VERSION 5.8 ;
BUSBITCHARS "[]" ;
DIVIDERCHAR "/" ;
UNITS
    DATABASE MICRONS 1000 ;
END UNITS

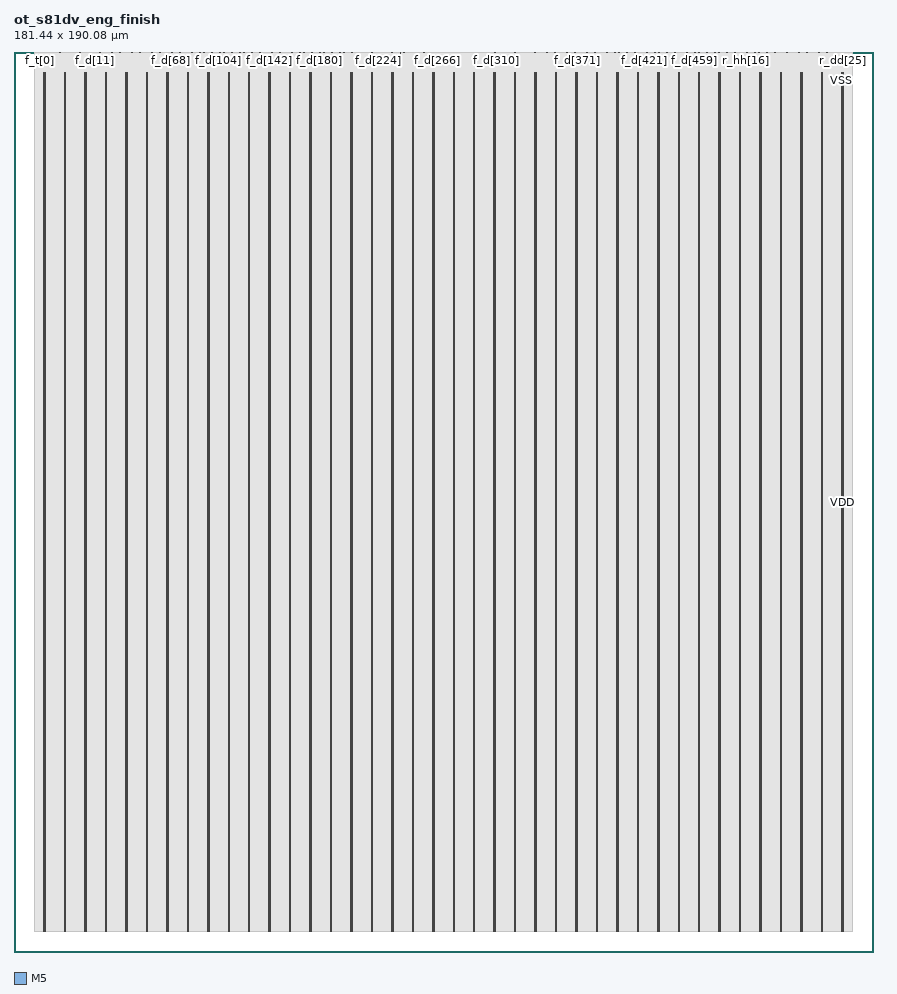
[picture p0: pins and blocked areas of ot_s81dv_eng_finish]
MACRO ot_s81dv_eng_finish
  FOREIGN ot_s81dv_eng_finish 0 0 ;
  CLASS BLOCK ;
  SIZE 181.44 BY 190.08 ;
  PIN clk
    DIRECTION INPUT ;
    USE SIGNAL ;
    PORT
      LAYER M5 ;
        RECT  81.54 189.6 81.588 190.08 ;
    END
  END clk
  PIN f_base[0]
    DIRECTION INPUT ;
    USE SIGNAL ;
    PORT
      LAYER M5 ;
        RECT  7.152 189.996 7.176 190.08 ;
    END
  END f_base[0]
  PIN f_base[10]
    DIRECTION INPUT ;
    USE SIGNAL ;
    PORT
      LAYER M5 ;
        RECT  9.936 189.996 9.96 190.08 ;
    END
  END f_base[10]
  PIN f_base[11]
    DIRECTION INPUT ;
    USE SIGNAL ;
    PORT
      LAYER M5 ;
        RECT  10.224 189.996 10.248 190.08 ;
    END
  END f_base[11]
  PIN f_base[12]
    DIRECTION INPUT ;
    USE SIGNAL ;
    PORT
      LAYER M5 ;
        RECT  10.512 189.996 10.536 190.08 ;
    END
  END f_base[12]
  PIN f_base[13]
    DIRECTION INPUT ;
    USE SIGNAL ;
    PORT
      LAYER M5 ;
        RECT  10.8 189.996 10.824 190.08 ;
    END
  END f_base[13]
  PIN f_base[14]
    DIRECTION INPUT ;
    USE SIGNAL ;
    PORT
      LAYER M5 ;
        RECT  11.088 189.996 11.112 190.08 ;
    END
  END f_base[14]
  PIN f_base[15]
    DIRECTION INPUT ;
    USE SIGNAL ;
    PORT
      LAYER M5 ;
        RECT  11.376 189.996 11.4 190.08 ;
    END
  END f_base[15]
  PIN f_base[16]
    DIRECTION INPUT ;
    USE SIGNAL ;
    PORT
      LAYER M5 ;
        RECT  11.664 189.996 11.688 190.08 ;
    END
  END f_base[16]
  PIN f_base[17]
    DIRECTION INPUT ;
    USE SIGNAL ;
    PORT
      LAYER M5 ;
        RECT  11.952 189.996 11.976 190.08 ;
    END
  END f_base[17]
  PIN f_base[18]
    DIRECTION INPUT ;
    USE SIGNAL ;
    PORT
      LAYER M5 ;
        RECT  12.192 189.996 12.216 190.08 ;
    END
  END f_base[18]
  PIN f_base[19]
    DIRECTION INPUT ;
    USE SIGNAL ;
    PORT
      LAYER M5 ;
        RECT  12.48 189.996 12.504 190.08 ;
    END
  END f_base[19]
  PIN f_base[1]
    DIRECTION INPUT ;
    USE SIGNAL ;
    PORT
      LAYER M5 ;
        RECT  7.44 189.996 7.464 190.08 ;
    END
  END f_base[1]
  PIN f_base[20]
    DIRECTION INPUT ;
    USE SIGNAL ;
    PORT
      LAYER M5 ;
        RECT  12.768 189.996 12.792 190.08 ;
    END
  END f_base[20]
  PIN f_base[21]
    DIRECTION INPUT ;
    USE SIGNAL ;
    PORT
      LAYER M5 ;
        RECT  13.056 189.996 13.08 190.08 ;
    END
  END f_base[21]
  PIN f_base[22]
    DIRECTION INPUT ;
    USE SIGNAL ;
    PORT
      LAYER M5 ;
        RECT  13.344 189.996 13.368 190.08 ;
    END
  END f_base[22]
  PIN f_base[23]
    DIRECTION INPUT ;
    USE SIGNAL ;
    PORT
      LAYER M5 ;
        RECT  13.632 189.996 13.656 190.08 ;
    END
  END f_base[23]
  PIN f_base[2]
    DIRECTION INPUT ;
    USE SIGNAL ;
    PORT
      LAYER M5 ;
        RECT  7.68 189.996 7.704 190.08 ;
    END
  END f_base[2]
  PIN f_base[3]
    DIRECTION INPUT ;
    USE SIGNAL ;
    PORT
      LAYER M5 ;
        RECT  7.968 189.996 7.992 190.08 ;
    END
  END f_base[3]
  PIN f_base[4]
    DIRECTION INPUT ;
    USE SIGNAL ;
    PORT
      LAYER M5 ;
        RECT  8.256 189.996 8.28 190.08 ;
    END
  END f_base[4]
  PIN f_base[5]
    DIRECTION INPUT ;
    USE SIGNAL ;
    PORT
      LAYER M5 ;
        RECT  8.544 189.996 8.568 190.08 ;
    END
  END f_base[5]
  PIN f_base[6]
    DIRECTION INPUT ;
    USE SIGNAL ;
    PORT
      LAYER M5 ;
        RECT  8.832 189.996 8.856 190.08 ;
    END
  END f_base[6]
  PIN f_base[7]
    DIRECTION INPUT ;
    USE SIGNAL ;
    PORT
      LAYER M5 ;
        RECT  9.12 189.996 9.144 190.08 ;
    END
  END f_base[7]
  PIN f_base[8]
    DIRECTION INPUT ;
    USE SIGNAL ;
    PORT
      LAYER M5 ;
        RECT  9.408 189.996 9.432 190.08 ;
    END
  END f_base[8]
  PIN f_base[9]
    DIRECTION INPUT ;
    USE SIGNAL ;
    PORT
      LAYER M5 ;
        RECT  9.696 189.996 9.72 190.08 ;
    END
  END f_base[9]
  PIN f_d[0]
    DIRECTION INPUT ;
    USE SIGNAL ;
    PORT
      LAYER M5 ;
        RECT  13.92 189.996 13.944 190.08 ;
    END
  END f_d[0]
  PIN f_d[100]
    DIRECTION INPUT ;
    USE SIGNAL ;
    PORT
      LAYER M5 ;
        RECT  42.096 189.996 42.12 190.08 ;
    END
  END f_d[100]
  PIN f_d[101]
    DIRECTION INPUT ;
    USE SIGNAL ;
    PORT
      LAYER M5 ;
        RECT  42.384 189.996 42.408 190.08 ;
    END
  END f_d[101]
  PIN f_d[102]
    DIRECTION INPUT ;
    USE SIGNAL ;
    PORT
      LAYER M5 ;
        RECT  42.624 189.996 42.648 190.08 ;
    END
  END f_d[102]
  PIN f_d[103]
    DIRECTION INPUT ;
    USE SIGNAL ;
    PORT
      LAYER M5 ;
        RECT  42.912 189.996 42.936 190.08 ;
    END
  END f_d[103]
  PIN f_d[104]
    DIRECTION INPUT ;
    USE SIGNAL ;
    PORT
      LAYER M5 ;
        RECT  43.2 189.996 43.224 190.08 ;
    END
  END f_d[104]
  PIN f_d[105]
    DIRECTION INPUT ;
    USE SIGNAL ;
    PORT
      LAYER M5 ;
        RECT  43.488 189.996 43.512 190.08 ;
    END
  END f_d[105]
  PIN f_d[106]
    DIRECTION INPUT ;
    USE SIGNAL ;
    PORT
      LAYER M5 ;
        RECT  43.776 189.996 43.8 190.08 ;
    END
  END f_d[106]
  PIN f_d[107]
    DIRECTION INPUT ;
    USE SIGNAL ;
    PORT
      LAYER M5 ;
        RECT  44.064 189.996 44.088 190.08 ;
    END
  END f_d[107]
  PIN f_d[108]
    DIRECTION INPUT ;
    USE SIGNAL ;
    PORT
      LAYER M5 ;
        RECT  44.352 189.996 44.376 190.08 ;
    END
  END f_d[108]
  PIN f_d[109]
    DIRECTION INPUT ;
    USE SIGNAL ;
    PORT
      LAYER M5 ;
        RECT  44.64 189.996 44.664 190.08 ;
    END
  END f_d[109]
  PIN f_d[10]
    DIRECTION INPUT ;
    USE SIGNAL ;
    PORT
      LAYER M5 ;
        RECT  16.704 189.996 16.728 190.08 ;
    END
  END f_d[10]
  PIN f_d[110]
    DIRECTION INPUT ;
    USE SIGNAL ;
    PORT
      LAYER M5 ;
        RECT  44.88 189.996 44.904 190.08 ;
    END
  END f_d[110]
  PIN f_d[111]
    DIRECTION INPUT ;
    USE SIGNAL ;
    PORT
      LAYER M5 ;
        RECT  45.168 189.996 45.192 190.08 ;
    END
  END f_d[111]
  PIN f_d[112]
    DIRECTION INPUT ;
    USE SIGNAL ;
    PORT
      LAYER M5 ;
        RECT  45.456 189.996 45.48 190.08 ;
    END
  END f_d[112]
  PIN f_d[113]
    DIRECTION INPUT ;
    USE SIGNAL ;
    PORT
      LAYER M5 ;
        RECT  45.744 189.996 45.768 190.08 ;
    END
  END f_d[113]
  PIN f_d[114]
    DIRECTION INPUT ;
    USE SIGNAL ;
    PORT
      LAYER M5 ;
        RECT  46.032 189.996 46.056 190.08 ;
    END
  END f_d[114]
  PIN f_d[115]
    DIRECTION INPUT ;
    USE SIGNAL ;
    PORT
      LAYER M5 ;
        RECT  46.32 189.996 46.344 190.08 ;
    END
  END f_d[115]
  PIN f_d[116]
    DIRECTION INPUT ;
    USE SIGNAL ;
    PORT
      LAYER M5 ;
        RECT  46.608 189.996 46.632 190.08 ;
    END
  END f_d[116]
  PIN f_d[117]
    DIRECTION INPUT ;
    USE SIGNAL ;
    PORT
      LAYER M5 ;
        RECT  46.896 189.996 46.92 190.08 ;
    END
  END f_d[117]
  PIN f_d[118]
    DIRECTION INPUT ;
    USE SIGNAL ;
    PORT
      LAYER M5 ;
        RECT  47.136 189.996 47.16 190.08 ;
    END
  END f_d[118]
  PIN f_d[119]
    DIRECTION INPUT ;
    USE SIGNAL ;
    PORT
      LAYER M5 ;
        RECT  47.424 189.996 47.448 190.08 ;
    END
  END f_d[119]
  PIN f_d[11]
    DIRECTION INPUT ;
    USE SIGNAL ;
    PORT
      LAYER M5 ;
        RECT  16.992 189.996 17.016 190.08 ;
    END
  END f_d[11]
  PIN f_d[120]
    DIRECTION INPUT ;
    USE SIGNAL ;
    PORT
      LAYER M5 ;
        RECT  47.712 189.996 47.736 190.08 ;
    END
  END f_d[120]
  PIN f_d[121]
    DIRECTION INPUT ;
    USE SIGNAL ;
    PORT
      LAYER M5 ;
        RECT  48 189.996 48.024 190.08 ;
    END
  END f_d[121]
  PIN f_d[122]
    DIRECTION INPUT ;
    USE SIGNAL ;
    PORT
      LAYER M5 ;
        RECT  48.288 189.996 48.312 190.08 ;
    END
  END f_d[122]
  PIN f_d[123]
    DIRECTION INPUT ;
    USE SIGNAL ;
    PORT
      LAYER M5 ;
        RECT  48.576 189.996 48.6 190.08 ;
    END
  END f_d[123]
  PIN f_d[124]
    DIRECTION INPUT ;
    USE SIGNAL ;
    PORT
      LAYER M5 ;
        RECT  48.864 189.996 48.888 190.08 ;
    END
  END f_d[124]
  PIN f_d[125]
    DIRECTION INPUT ;
    USE SIGNAL ;
    PORT
      LAYER M5 ;
        RECT  49.152 189.996 49.176 190.08 ;
    END
  END f_d[125]
  PIN f_d[126]
    DIRECTION INPUT ;
    USE SIGNAL ;
    PORT
      LAYER M5 ;
        RECT  49.392 189.996 49.416 190.08 ;
    END
  END f_d[126]
  PIN f_d[127]
    DIRECTION INPUT ;
    USE SIGNAL ;
    PORT
      LAYER M5 ;
        RECT  49.68 189.996 49.704 190.08 ;
    END
  END f_d[127]
  PIN f_d[128]
    DIRECTION INPUT ;
    USE SIGNAL ;
    PORT
      LAYER M5 ;
        RECT  49.968 189.996 49.992 190.08 ;
    END
  END f_d[128]
  PIN f_d[129]
    DIRECTION INPUT ;
    USE SIGNAL ;
    PORT
      LAYER M5 ;
        RECT  50.256 189.996 50.28 190.08 ;
    END
  END f_d[129]
  PIN f_d[12]
    DIRECTION INPUT ;
    USE SIGNAL ;
    PORT
      LAYER M5 ;
        RECT  17.28 189.996 17.304 190.08 ;
    END
  END f_d[12]
  PIN f_d[130]
    DIRECTION INPUT ;
    USE SIGNAL ;
    PORT
      LAYER M5 ;
        RECT  50.544 189.996 50.568 190.08 ;
    END
  END f_d[130]
  PIN f_d[131]
    DIRECTION INPUT ;
    USE SIGNAL ;
    PORT
      LAYER M5 ;
        RECT  50.832 189.996 50.856 190.08 ;
    END
  END f_d[131]
  PIN f_d[132]
    DIRECTION INPUT ;
    USE SIGNAL ;
    PORT
      LAYER M5 ;
        RECT  51.12 189.996 51.144 190.08 ;
    END
  END f_d[132]
  PIN f_d[133]
    DIRECTION INPUT ;
    USE SIGNAL ;
    PORT
      LAYER M5 ;
        RECT  51.36 189.996 51.384 190.08 ;
    END
  END f_d[133]
  PIN f_d[134]
    DIRECTION INPUT ;
    USE SIGNAL ;
    PORT
      LAYER M5 ;
        RECT  51.648 189.996 51.672 190.08 ;
    END
  END f_d[134]
  PIN f_d[135]
    DIRECTION INPUT ;
    USE SIGNAL ;
    PORT
      LAYER M5 ;
        RECT  51.936 189.996 51.96 190.08 ;
    END
  END f_d[135]
  PIN f_d[136]
    DIRECTION INPUT ;
    USE SIGNAL ;
    PORT
      LAYER M5 ;
        RECT  52.224 189.996 52.248 190.08 ;
    END
  END f_d[136]
  PIN f_d[137]
    DIRECTION INPUT ;
    USE SIGNAL ;
    PORT
      LAYER M5 ;
        RECT  52.512 189.996 52.536 190.08 ;
    END
  END f_d[137]
  PIN f_d[138]
    DIRECTION INPUT ;
    USE SIGNAL ;
    PORT
      LAYER M5 ;
        RECT  52.8 189.996 52.824 190.08 ;
    END
  END f_d[138]
  PIN f_d[139]
    DIRECTION INPUT ;
    USE SIGNAL ;
    PORT
      LAYER M5 ;
        RECT  53.088 189.996 53.112 190.08 ;
    END
  END f_d[139]
  PIN f_d[13]
    DIRECTION INPUT ;
    USE SIGNAL ;
    PORT
      LAYER M5 ;
        RECT  17.568 189.996 17.592 190.08 ;
    END
  END f_d[13]
  PIN f_d[140]
    DIRECTION INPUT ;
    USE SIGNAL ;
    PORT
      LAYER M5 ;
        RECT  53.376 189.996 53.4 190.08 ;
    END
  END f_d[140]
  PIN f_d[141]
    DIRECTION INPUT ;
    USE SIGNAL ;
    PORT
      LAYER M5 ;
        RECT  53.616 189.996 53.64 190.08 ;
    END
  END f_d[141]
  PIN f_d[142]
    DIRECTION INPUT ;
    USE SIGNAL ;
    PORT
      LAYER M5 ;
        RECT  53.904 189.996 53.928 190.08 ;
    END
  END f_d[142]
  PIN f_d[143]
    DIRECTION INPUT ;
    USE SIGNAL ;
    PORT
      LAYER M5 ;
        RECT  54.192 189.996 54.216 190.08 ;
    END
  END f_d[143]
  PIN f_d[144]
    DIRECTION INPUT ;
    USE SIGNAL ;
    PORT
      LAYER M5 ;
        RECT  54.48 189.996 54.504 190.08 ;
    END
  END f_d[144]
  PIN f_d[145]
    DIRECTION INPUT ;
    USE SIGNAL ;
    PORT
      LAYER M5 ;
        RECT  54.768 189.996 54.792 190.08 ;
    END
  END f_d[145]
  PIN f_d[146]
    DIRECTION INPUT ;
    USE SIGNAL ;
    PORT
      LAYER M5 ;
        RECT  55.056 189.996 55.08 190.08 ;
    END
  END f_d[146]
  PIN f_d[147]
    DIRECTION INPUT ;
    USE SIGNAL ;
    PORT
      LAYER M5 ;
        RECT  55.344 189.996 55.368 190.08 ;
    END
  END f_d[147]
  PIN f_d[148]
    DIRECTION INPUT ;
    USE SIGNAL ;
    PORT
      LAYER M5 ;
        RECT  55.632 189.996 55.656 190.08 ;
    END
  END f_d[148]
  PIN f_d[149]
    DIRECTION INPUT ;
    USE SIGNAL ;
    PORT
      LAYER M5 ;
        RECT  55.872 189.996 55.896 190.08 ;
    END
  END f_d[149]
  PIN f_d[14]
    DIRECTION INPUT ;
    USE SIGNAL ;
    PORT
      LAYER M5 ;
        RECT  17.856 189.996 17.88 190.08 ;
    END
  END f_d[14]
  PIN f_d[150]
    DIRECTION INPUT ;
    USE SIGNAL ;
    PORT
      LAYER M5 ;
        RECT  56.16 189.996 56.184 190.08 ;
    END
  END f_d[150]
  PIN f_d[151]
    DIRECTION INPUT ;
    USE SIGNAL ;
    PORT
      LAYER M5 ;
        RECT  56.448 189.996 56.472 190.08 ;
    END
  END f_d[151]
  PIN f_d[152]
    DIRECTION INPUT ;
    USE SIGNAL ;
    PORT
      LAYER M5 ;
        RECT  56.736 189.996 56.76 190.08 ;
    END
  END f_d[152]
  PIN f_d[153]
    DIRECTION INPUT ;
    USE SIGNAL ;
    PORT
      LAYER M5 ;
        RECT  57.024 189.996 57.048 190.08 ;
    END
  END f_d[153]
  PIN f_d[154]
    DIRECTION INPUT ;
    USE SIGNAL ;
    PORT
      LAYER M5 ;
        RECT  57.312 189.996 57.336 190.08 ;
    END
  END f_d[154]
  PIN f_d[155]
    DIRECTION INPUT ;
    USE SIGNAL ;
    PORT
      LAYER M5 ;
        RECT  57.6 189.996 57.624 190.08 ;
    END
  END f_d[155]
  PIN f_d[156]
    DIRECTION INPUT ;
    USE SIGNAL ;
    PORT
      LAYER M5 ;
        RECT  57.888 189.996 57.912 190.08 ;
    END
  END f_d[156]
  PIN f_d[157]
    DIRECTION INPUT ;
    USE SIGNAL ;
    PORT
      LAYER M5 ;
        RECT  58.128 189.996 58.152 190.08 ;
    END
  END f_d[157]
  PIN f_d[158]
    DIRECTION INPUT ;
    USE SIGNAL ;
    PORT
      LAYER M5 ;
        RECT  58.416 189.996 58.44 190.08 ;
    END
  END f_d[158]
  PIN f_d[159]
    DIRECTION INPUT ;
    USE SIGNAL ;
    PORT
      LAYER M5 ;
        RECT  58.704 189.996 58.728 190.08 ;
    END
  END f_d[159]
  PIN f_d[15]
    DIRECTION INPUT ;
    USE SIGNAL ;
    PORT
      LAYER M5 ;
        RECT  18.144 189.996 18.168 190.08 ;
    END
  END f_d[15]
  PIN f_d[160]
    DIRECTION INPUT ;
    USE SIGNAL ;
    PORT
      LAYER M5 ;
        RECT  58.992 189.996 59.016 190.08 ;
    END
  END f_d[160]
  PIN f_d[161]
    DIRECTION INPUT ;
    USE SIGNAL ;
    PORT
      LAYER M5 ;
        RECT  59.28 189.996 59.304 190.08 ;
    END
  END f_d[161]
  PIN f_d[162]
    DIRECTION INPUT ;
    USE SIGNAL ;
    PORT
      LAYER M5 ;
        RECT  59.568 189.996 59.592 190.08 ;
    END
  END f_d[162]
  PIN f_d[163]
    DIRECTION INPUT ;
    USE SIGNAL ;
    PORT
      LAYER M5 ;
        RECT  59.856 189.996 59.88 190.08 ;
    END
  END f_d[163]
  PIN f_d[164]
    DIRECTION INPUT ;
    USE SIGNAL ;
    PORT
      LAYER M5 ;
        RECT  60.096 189.996 60.12 190.08 ;
    END
  END f_d[164]
  PIN f_d[165]
    DIRECTION INPUT ;
    USE SIGNAL ;
    PORT
      LAYER M5 ;
        RECT  60.384 189.996 60.408 190.08 ;
    END
  END f_d[165]
  PIN f_d[166]
    DIRECTION INPUT ;
    USE SIGNAL ;
    PORT
      LAYER M5 ;
        RECT  60.672 189.996 60.696 190.08 ;
    END
  END f_d[166]
  PIN f_d[167]
    DIRECTION INPUT ;
    USE SIGNAL ;
    PORT
      LAYER M5 ;
        RECT  60.96 189.996 60.984 190.08 ;
    END
  END f_d[167]
  PIN f_d[168]
    DIRECTION INPUT ;
    USE SIGNAL ;
    PORT
      LAYER M5 ;
        RECT  61.248 189.996 61.272 190.08 ;
    END
  END f_d[168]
  PIN f_d[169]
    DIRECTION INPUT ;
    USE SIGNAL ;
    PORT
      LAYER M5 ;
        RECT  61.536 189.996 61.56 190.08 ;
    END
  END f_d[169]
  PIN f_d[16]
    DIRECTION INPUT ;
    USE SIGNAL ;
    PORT
      LAYER M5 ;
        RECT  18.432 189.996 18.456 190.08 ;
    END
  END f_d[16]
  PIN f_d[170]
    DIRECTION INPUT ;
    USE SIGNAL ;
    PORT
      LAYER M5 ;
        RECT  61.824 189.996 61.848 190.08 ;
    END
  END f_d[170]
  PIN f_d[171]
    DIRECTION INPUT ;
    USE SIGNAL ;
    PORT
      LAYER M5 ;
        RECT  62.112 189.996 62.136 190.08 ;
    END
  END f_d[171]
  PIN f_d[172]
    DIRECTION INPUT ;
    USE SIGNAL ;
    PORT
      LAYER M5 ;
        RECT  62.352 189.996 62.376 190.08 ;
    END
  END f_d[172]
  PIN f_d[173]
    DIRECTION INPUT ;
    USE SIGNAL ;
    PORT
      LAYER M5 ;
        RECT  62.64 189.996 62.664 190.08 ;
    END
  END f_d[173]
  PIN f_d[174]
    DIRECTION INPUT ;
    USE SIGNAL ;
    PORT
      LAYER M5 ;
        RECT  62.928 189.996 62.952 190.08 ;
    END
  END f_d[174]
  PIN f_d[175]
    DIRECTION INPUT ;
    USE SIGNAL ;
    PORT
      LAYER M5 ;
        RECT  63.216 189.996 63.24 190.08 ;
    END
  END f_d[175]
  PIN f_d[176]
    DIRECTION INPUT ;
    USE SIGNAL ;
    PORT
      LAYER M5 ;
        RECT  63.504 189.996 63.528 190.08 ;
    END
  END f_d[176]
  PIN f_d[177]
    DIRECTION INPUT ;
    USE SIGNAL ;
    PORT
      LAYER M5 ;
        RECT  63.792 189.996 63.816 190.08 ;
    END
  END f_d[177]
  PIN f_d[178]
    DIRECTION INPUT ;
    USE SIGNAL ;
    PORT
      LAYER M5 ;
        RECT  64.08 189.996 64.104 190.08 ;
    END
  END f_d[178]
  PIN f_d[179]
    DIRECTION INPUT ;
    USE SIGNAL ;
    PORT
      LAYER M5 ;
        RECT  64.368 189.996 64.392 190.08 ;
    END
  END f_d[179]
  PIN f_d[17]
    DIRECTION INPUT ;
    USE SIGNAL ;
    PORT
      LAYER M5 ;
        RECT  18.672 189.996 18.696 190.08 ;
    END
  END f_d[17]
  PIN f_d[180]
    DIRECTION INPUT ;
    USE SIGNAL ;
    PORT
      LAYER M5 ;
        RECT  64.608 189.996 64.632 190.08 ;
    END
  END f_d[180]
  PIN f_d[181]
    DIRECTION INPUT ;
    USE SIGNAL ;
    PORT
      LAYER M5 ;
        RECT  64.896 189.996 64.92 190.08 ;
    END
  END f_d[181]
  PIN f_d[182]
    DIRECTION INPUT ;
    USE SIGNAL ;
    PORT
      LAYER M5 ;
        RECT  65.184 189.996 65.208 190.08 ;
    END
  END f_d[182]
  PIN f_d[183]
    DIRECTION INPUT ;
    USE SIGNAL ;
    PORT
      LAYER M5 ;
        RECT  65.472 189.996 65.496 190.08 ;
    END
  END f_d[183]
  PIN f_d[184]
    DIRECTION INPUT ;
    USE SIGNAL ;
    PORT
      LAYER M5 ;
        RECT  65.76 189.996 65.784 190.08 ;
    END
  END f_d[184]
  PIN f_d[185]
    DIRECTION INPUT ;
    USE SIGNAL ;
    PORT
      LAYER M5 ;
        RECT  66.048 189.996 66.072 190.08 ;
    END
  END f_d[185]
  PIN f_d[186]
    DIRECTION INPUT ;
    USE SIGNAL ;
    PORT
      LAYER M5 ;
        RECT  66.336 189.996 66.36 190.08 ;
    END
  END f_d[186]
  PIN f_d[187]
    DIRECTION INPUT ;
    USE SIGNAL ;
    PORT
      LAYER M5 ;
        RECT  66.624 189.996 66.648 190.08 ;
    END
  END f_d[187]
  PIN f_d[188]
    DIRECTION INPUT ;
    USE SIGNAL ;
    PORT
      LAYER M5 ;
        RECT  66.864 189.996 66.888 190.08 ;
    END
  END f_d[188]
  PIN f_d[189]
    DIRECTION INPUT ;
    USE SIGNAL ;
    PORT
      LAYER M5 ;
        RECT  67.152 189.996 67.176 190.08 ;
    END
  END f_d[189]
  PIN f_d[18]
    DIRECTION INPUT ;
    USE SIGNAL ;
    PORT
      LAYER M5 ;
        RECT  18.96 189.996 18.984 190.08 ;
    END
  END f_d[18]
  PIN f_d[190]
    DIRECTION INPUT ;
    USE SIGNAL ;
    PORT
      LAYER M5 ;
        RECT  67.44 189.996 67.464 190.08 ;
    END
  END f_d[190]
  PIN f_d[191]
    DIRECTION INPUT ;
    USE SIGNAL ;
    PORT
      LAYER M5 ;
        RECT  67.728 189.996 67.752 190.08 ;
    END
  END f_d[191]
  PIN f_d[192]
    DIRECTION INPUT ;
    USE SIGNAL ;
    PORT
      LAYER M5 ;
        RECT  68.016 189.996 68.04 190.08 ;
    END
  END f_d[192]
  PIN f_d[193]
    DIRECTION INPUT ;
    USE SIGNAL ;
    PORT
      LAYER M5 ;
        RECT  68.304 189.996 68.328 190.08 ;
    END
  END f_d[193]
  PIN f_d[194]
    DIRECTION INPUT ;
    USE SIGNAL ;
    PORT
      LAYER M5 ;
        RECT  68.592 189.996 68.616 190.08 ;
    END
  END f_d[194]
  PIN f_d[195]
    DIRECTION INPUT ;
    USE SIGNAL ;
    PORT
      LAYER M5 ;
        RECT  68.832 189.996 68.856 190.08 ;
    END
  END f_d[195]
  PIN f_d[196]
    DIRECTION INPUT ;
    USE SIGNAL ;
    PORT
      LAYER M5 ;
        RECT  69.12 189.996 69.144 190.08 ;
    END
  END f_d[196]
  PIN f_d[197]
    DIRECTION INPUT ;
    USE SIGNAL ;
    PORT
      LAYER M5 ;
        RECT  69.408 189.996 69.432 190.08 ;
    END
  END f_d[197]
  PIN f_d[198]
    DIRECTION INPUT ;
    USE SIGNAL ;
    PORT
      LAYER M5 ;
        RECT  69.696 189.996 69.72 190.08 ;
    END
  END f_d[198]
  PIN f_d[199]
    DIRECTION INPUT ;
    USE SIGNAL ;
    PORT
      LAYER M5 ;
        RECT  69.984 189.996 70.008 190.08 ;
    END
  END f_d[199]
  PIN f_d[19]
    DIRECTION INPUT ;
    USE SIGNAL ;
    PORT
      LAYER M5 ;
        RECT  19.248 189.996 19.272 190.08 ;
    END
  END f_d[19]
  PIN f_d[1]
    DIRECTION INPUT ;
    USE SIGNAL ;
    PORT
      LAYER M5 ;
        RECT  14.16 189.996 14.184 190.08 ;
    END
  END f_d[1]
  PIN f_d[200]
    DIRECTION INPUT ;
    USE SIGNAL ;
    PORT
      LAYER M5 ;
        RECT  70.272 189.996 70.296 190.08 ;
    END
  END f_d[200]
  PIN f_d[201]
    DIRECTION INPUT ;
    USE SIGNAL ;
    PORT
      LAYER M5 ;
        RECT  70.56 189.996 70.584 190.08 ;
    END
  END f_d[201]
  PIN f_d[202]
    DIRECTION INPUT ;
    USE SIGNAL ;
    PORT
      LAYER M5 ;
        RECT  70.848 189.996 70.872 190.08 ;
    END
  END f_d[202]
  PIN f_d[203]
    DIRECTION INPUT ;
    USE SIGNAL ;
    PORT
      LAYER M5 ;
        RECT  71.088 189.996 71.112 190.08 ;
    END
  END f_d[203]
  PIN f_d[204]
    DIRECTION INPUT ;
    USE SIGNAL ;
    PORT
      LAYER M5 ;
        RECT  71.376 189.996 71.4 190.08 ;
    END
  END f_d[204]
  PIN f_d[205]
    DIRECTION INPUT ;
    USE SIGNAL ;
    PORT
      LAYER M5 ;
        RECT  71.664 189.996 71.688 190.08 ;
    END
  END f_d[205]
  PIN f_d[206]
    DIRECTION INPUT ;
    USE SIGNAL ;
    PORT
      LAYER M5 ;
        RECT  71.952 189.996 71.976 190.08 ;
    END
  END f_d[206]
  PIN f_d[207]
    DIRECTION INPUT ;
    USE SIGNAL ;
    PORT
      LAYER M5 ;
        RECT  72.24 189.996 72.264 190.08 ;
    END
  END f_d[207]
  PIN f_d[208]
    DIRECTION INPUT ;
    USE SIGNAL ;
    PORT
      LAYER M5 ;
        RECT  72.528 189.996 72.552 190.08 ;
    END
  END f_d[208]
  PIN f_d[209]
    DIRECTION INPUT ;
    USE SIGNAL ;
    PORT
      LAYER M5 ;
        RECT  72.816 189.996 72.84 190.08 ;
    END
  END f_d[209]
  PIN f_d[20]
    DIRECTION INPUT ;
    USE SIGNAL ;
    PORT
      LAYER M5 ;
        RECT  19.536 189.996 19.56 190.08 ;
    END
  END f_d[20]
  PIN f_d[210]
    DIRECTION INPUT ;
    USE SIGNAL ;
    PORT
      LAYER M5 ;
        RECT  73.104 189.996 73.128 190.08 ;
    END
  END f_d[210]
  PIN f_d[211]
    DIRECTION INPUT ;
    USE SIGNAL ;
    PORT
      LAYER M5 ;
        RECT  73.344 189.996 73.368 190.08 ;
    END
  END f_d[211]
  PIN f_d[212]
    DIRECTION INPUT ;
    USE SIGNAL ;
    PORT
      LAYER M5 ;
        RECT  73.632 189.996 73.656 190.08 ;
    END
  END f_d[212]
  PIN f_d[213]
    DIRECTION INPUT ;
    USE SIGNAL ;
    PORT
      LAYER M5 ;
        RECT  73.92 189.996 73.944 190.08 ;
    END
  END f_d[213]
  PIN f_d[214]
    DIRECTION INPUT ;
    USE SIGNAL ;
    PORT
      LAYER M5 ;
        RECT  74.208 189.996 74.232 190.08 ;
    END
  END f_d[214]
  PIN f_d[215]
    DIRECTION INPUT ;
    USE SIGNAL ;
    PORT
      LAYER M5 ;
        RECT  74.496 189.996 74.52 190.08 ;
    END
  END f_d[215]
  PIN f_d[216]
    DIRECTION INPUT ;
    USE SIGNAL ;
    PORT
      LAYER M5 ;
        RECT  74.784 189.996 74.808 190.08 ;
    END
  END f_d[216]
  PIN f_d[217]
    DIRECTION INPUT ;
    USE SIGNAL ;
    PORT
      LAYER M5 ;
        RECT  75.072 189.996 75.096 190.08 ;
    END
  END f_d[217]
  PIN f_d[218]
    DIRECTION INPUT ;
    USE SIGNAL ;
    PORT
      LAYER M5 ;
        RECT  75.36 189.996 75.384 190.08 ;
    END
  END f_d[218]
  PIN f_d[219]
    DIRECTION INPUT ;
    USE SIGNAL ;
    PORT
      LAYER M5 ;
        RECT  75.6 189.996 75.624 190.08 ;
    END
  END f_d[219]
  PIN f_d[21]
    DIRECTION INPUT ;
    USE SIGNAL ;
    PORT
      LAYER M5 ;
        RECT  19.824 189.996 19.848 190.08 ;
    END
  END f_d[21]
  PIN f_d[220]
    DIRECTION INPUT ;
    USE SIGNAL ;
    PORT
      LAYER M5 ;
        RECT  75.888 189.996 75.912 190.08 ;
    END
  END f_d[220]
  PIN f_d[221]
    DIRECTION INPUT ;
    USE SIGNAL ;
    PORT
      LAYER M5 ;
        RECT  76.176 189.996 76.2 190.08 ;
    END
  END f_d[221]
  PIN f_d[222]
    DIRECTION INPUT ;
    USE SIGNAL ;
    PORT
      LAYER M5 ;
        RECT  76.464 189.996 76.488 190.08 ;
    END
  END f_d[222]
  PIN f_d[223]
    DIRECTION INPUT ;
    USE SIGNAL ;
    PORT
      LAYER M5 ;
        RECT  76.752 189.996 76.776 190.08 ;
    END
  END f_d[223]
  PIN f_d[224]
    DIRECTION INPUT ;
    USE SIGNAL ;
    PORT
      LAYER M5 ;
        RECT  77.04 189.996 77.064 190.08 ;
    END
  END f_d[224]
  PIN f_d[225]
    DIRECTION INPUT ;
    USE SIGNAL ;
    PORT
      LAYER M5 ;
        RECT  77.328 189.996 77.352 190.08 ;
    END
  END f_d[225]
  PIN f_d[226]
    DIRECTION INPUT ;
    USE SIGNAL ;
    PORT
      LAYER M5 ;
        RECT  77.568 189.996 77.592 190.08 ;
    END
  END f_d[226]
  PIN f_d[227]
    DIRECTION INPUT ;
    USE SIGNAL ;
    PORT
      LAYER M5 ;
        RECT  77.856 189.996 77.88 190.08 ;
    END
  END f_d[227]
  PIN f_d[228]
    DIRECTION INPUT ;
    USE SIGNAL ;
    PORT
      LAYER M5 ;
        RECT  78.144 189.996 78.168 190.08 ;
    END
  END f_d[228]
  PIN f_d[229]
    DIRECTION INPUT ;
    USE SIGNAL ;
    PORT
      LAYER M5 ;
        RECT  78.432 189.996 78.456 190.08 ;
    END
  END f_d[229]
  PIN f_d[22]
    DIRECTION INPUT ;
    USE SIGNAL ;
    PORT
      LAYER M5 ;
        RECT  20.112 189.996 20.136 190.08 ;
    END
  END f_d[22]
  PIN f_d[230]
    DIRECTION INPUT ;
    USE SIGNAL ;
    PORT
      LAYER M5 ;
        RECT  78.72 189.996 78.744 190.08 ;
    END
  END f_d[230]
  PIN f_d[231]
    DIRECTION INPUT ;
    USE SIGNAL ;
    PORT
      LAYER M5 ;
        RECT  79.008 189.996 79.032 190.08 ;
    END
  END f_d[231]
  PIN f_d[232]
    DIRECTION INPUT ;
    USE SIGNAL ;
    PORT
      LAYER M5 ;
        RECT  79.296 189.996 79.32 190.08 ;
    END
  END f_d[232]
  PIN f_d[233]
    DIRECTION INPUT ;
    USE SIGNAL ;
    PORT
      LAYER M5 ;
        RECT  79.584 189.996 79.608 190.08 ;
    END
  END f_d[233]
  PIN f_d[234]
    DIRECTION INPUT ;
    USE SIGNAL ;
    PORT
      LAYER M5 ;
        RECT  79.824 189.996 79.848 190.08 ;
    END
  END f_d[234]
  PIN f_d[235]
    DIRECTION INPUT ;
    USE SIGNAL ;
    PORT
      LAYER M5 ;
        RECT  80.112 189.996 80.136 190.08 ;
    END
  END f_d[235]
  PIN f_d[236]
    DIRECTION INPUT ;
    USE SIGNAL ;
    PORT
      LAYER M5 ;
        RECT  80.4 189.996 80.424 190.08 ;
    END
  END f_d[236]
  PIN f_d[237]
    DIRECTION INPUT ;
    USE SIGNAL ;
    PORT
      LAYER M5 ;
        RECT  80.688 189.996 80.712 190.08 ;
    END
  END f_d[237]
  PIN f_d[238]
    DIRECTION INPUT ;
    USE SIGNAL ;
    PORT
      LAYER M5 ;
        RECT  80.976 189.996 81 190.08 ;
    END
  END f_d[238]
  PIN f_d[239]
    DIRECTION INPUT ;
    USE SIGNAL ;
    PORT
      LAYER M5 ;
        RECT  81.264 189.996 81.288 190.08 ;
    END
  END f_d[239]
  PIN f_d[23]
    DIRECTION INPUT ;
    USE SIGNAL ;
    PORT
      LAYER M5 ;
        RECT  20.4 189.996 20.424 190.08 ;
    END
  END f_d[23]
  PIN f_d[240]
    DIRECTION INPUT ;
    USE SIGNAL ;
    PORT
      LAYER M5 ;
        RECT  82.08 189.996 82.104 190.08 ;
    END
  END f_d[240]
  PIN f_d[241]
    DIRECTION INPUT ;
    USE SIGNAL ;
    PORT
      LAYER M5 ;
        RECT  82.368 189.996 82.392 190.08 ;
    END
  END f_d[241]
  PIN f_d[242]
    DIRECTION INPUT ;
    USE SIGNAL ;
    PORT
      LAYER M5 ;
        RECT  82.656 189.996 82.68 190.08 ;
    END
  END f_d[242]
  PIN f_d[243]
    DIRECTION INPUT ;
    USE SIGNAL ;
    PORT
      LAYER M5 ;
        RECT  82.944 189.996 82.968 190.08 ;
    END
  END f_d[243]
  PIN f_d[244]
    DIRECTION INPUT ;
    USE SIGNAL ;
    PORT
      LAYER M5 ;
        RECT  83.232 189.996 83.256 190.08 ;
    END
  END f_d[244]
  PIN f_d[245]
    DIRECTION INPUT ;
    USE SIGNAL ;
    PORT
      LAYER M5 ;
        RECT  83.52 189.996 83.544 190.08 ;
    END
  END f_d[245]
  PIN f_d[246]
    DIRECTION INPUT ;
    USE SIGNAL ;
    PORT
      LAYER M5 ;
        RECT  83.808 189.996 83.832 190.08 ;
    END
  END f_d[246]
  PIN f_d[247]
    DIRECTION INPUT ;
    USE SIGNAL ;
    PORT
      LAYER M5 ;
        RECT  84.096 189.996 84.12 190.08 ;
    END
  END f_d[247]
  PIN f_d[248]
    DIRECTION INPUT ;
    USE SIGNAL ;
    PORT
      LAYER M5 ;
        RECT  84.336 189.996 84.36 190.08 ;
    END
  END f_d[248]
  PIN f_d[249]
    DIRECTION INPUT ;
    USE SIGNAL ;
    PORT
      LAYER M5 ;
        RECT  84.624 189.996 84.648 190.08 ;
    END
  END f_d[249]
  PIN f_d[24]
    DIRECTION INPUT ;
    USE SIGNAL ;
    PORT
      LAYER M5 ;
        RECT  20.688 189.996 20.712 190.08 ;
    END
  END f_d[24]
  PIN f_d[250]
    DIRECTION INPUT ;
    USE SIGNAL ;
    PORT
      LAYER M5 ;
        RECT  84.912 189.996 84.936 190.08 ;
    END
  END f_d[250]
  PIN f_d[251]
    DIRECTION INPUT ;
    USE SIGNAL ;
    PORT
      LAYER M5 ;
        RECT  85.2 189.996 85.224 190.08 ;
    END
  END f_d[251]
  PIN f_d[252]
    DIRECTION INPUT ;
    USE SIGNAL ;
    PORT
      LAYER M5 ;
        RECT  85.488 189.996 85.512 190.08 ;
    END
  END f_d[252]
  PIN f_d[253]
    DIRECTION INPUT ;
    USE SIGNAL ;
    PORT
      LAYER M5 ;
        RECT  85.776 189.996 85.8 190.08 ;
    END
  END f_d[253]
  PIN f_d[254]
    DIRECTION INPUT ;
    USE SIGNAL ;
    PORT
      LAYER M5 ;
        RECT  86.064 189.996 86.088 190.08 ;
    END
  END f_d[254]
  PIN f_d[255]
    DIRECTION INPUT ;
    USE SIGNAL ;
    PORT
      LAYER M5 ;
        RECT  86.304 189.996 86.328 190.08 ;
    END
  END f_d[255]
  PIN f_d[256]
    DIRECTION INPUT ;
    USE SIGNAL ;
    PORT
      LAYER M5 ;
        RECT  86.592 189.996 86.616 190.08 ;
    END
  END f_d[256]
  PIN f_d[257]
    DIRECTION INPUT ;
    USE SIGNAL ;
    PORT
      LAYER M5 ;
        RECT  86.88 189.996 86.904 190.08 ;
    END
  END f_d[257]
  PIN f_d[258]
    DIRECTION INPUT ;
    USE SIGNAL ;
    PORT
      LAYER M5 ;
        RECT  87.168 189.996 87.192 190.08 ;
    END
  END f_d[258]
  PIN f_d[259]
    DIRECTION INPUT ;
    USE SIGNAL ;
    PORT
      LAYER M5 ;
        RECT  87.456 189.996 87.48 190.08 ;
    END
  END f_d[259]
  PIN f_d[25]
    DIRECTION INPUT ;
    USE SIGNAL ;
    PORT
      LAYER M5 ;
        RECT  20.928 189.996 20.952 190.08 ;
    END
  END f_d[25]
  PIN f_d[260]
    DIRECTION INPUT ;
    USE SIGNAL ;
    PORT
      LAYER M5 ;
        RECT  87.744 189.996 87.768 190.08 ;
    END
  END f_d[260]
  PIN f_d[261]
    DIRECTION INPUT ;
    USE SIGNAL ;
    PORT
      LAYER M5 ;
        RECT  88.032 189.996 88.056 190.08 ;
    END
  END f_d[261]
  PIN f_d[262]
    DIRECTION INPUT ;
    USE SIGNAL ;
    PORT
      LAYER M5 ;
        RECT  88.32 189.996 88.344 190.08 ;
    END
  END f_d[262]
  PIN f_d[263]
    DIRECTION INPUT ;
    USE SIGNAL ;
    PORT
      LAYER M5 ;
        RECT  88.56 189.996 88.584 190.08 ;
    END
  END f_d[263]
  PIN f_d[264]
    DIRECTION INPUT ;
    USE SIGNAL ;
    PORT
      LAYER M5 ;
        RECT  88.848 189.996 88.872 190.08 ;
    END
  END f_d[264]
  PIN f_d[265]
    DIRECTION INPUT ;
    USE SIGNAL ;
    PORT
      LAYER M5 ;
        RECT  89.136 189.996 89.16 190.08 ;
    END
  END f_d[265]
  PIN f_d[266]
    DIRECTION INPUT ;
    USE SIGNAL ;
    PORT
      LAYER M5 ;
        RECT  89.424 189.996 89.448 190.08 ;
    END
  END f_d[266]
  PIN f_d[267]
    DIRECTION INPUT ;
    USE SIGNAL ;
    PORT
      LAYER M5 ;
        RECT  89.712 189.996 89.736 190.08 ;
    END
  END f_d[267]
  PIN f_d[268]
    DIRECTION INPUT ;
    USE SIGNAL ;
    PORT
      LAYER M5 ;
        RECT  90 189.996 90.024 190.08 ;
    END
  END f_d[268]
  PIN f_d[269]
    DIRECTION INPUT ;
    USE SIGNAL ;
    PORT
      LAYER M5 ;
        RECT  90.288 189.996 90.312 190.08 ;
    END
  END f_d[269]
  PIN f_d[26]
    DIRECTION INPUT ;
    USE SIGNAL ;
    PORT
      LAYER M5 ;
        RECT  21.216 189.996 21.24 190.08 ;
    END
  END f_d[26]
  PIN f_d[270]
    DIRECTION INPUT ;
    USE SIGNAL ;
    PORT
      LAYER M5 ;
        RECT  90.576 189.996 90.6 190.08 ;
    END
  END f_d[270]
  PIN f_d[271]
    DIRECTION INPUT ;
    USE SIGNAL ;
    PORT
      LAYER M5 ;
        RECT  90.816 189.996 90.84 190.08 ;
    END
  END f_d[271]
  PIN f_d[272]
    DIRECTION INPUT ;
    USE SIGNAL ;
    PORT
      LAYER M5 ;
        RECT  91.104 189.996 91.128 190.08 ;
    END
  END f_d[272]
  PIN f_d[273]
    DIRECTION INPUT ;
    USE SIGNAL ;
    PORT
      LAYER M5 ;
        RECT  91.392 189.996 91.416 190.08 ;
    END
  END f_d[273]
  PIN f_d[274]
    DIRECTION INPUT ;
    USE SIGNAL ;
    PORT
      LAYER M5 ;
        RECT  91.68 189.996 91.704 190.08 ;
    END
  END f_d[274]
  PIN f_d[275]
    DIRECTION INPUT ;
    USE SIGNAL ;
    PORT
      LAYER M5 ;
        RECT  91.968 189.996 91.992 190.08 ;
    END
  END f_d[275]
  PIN f_d[276]
    DIRECTION INPUT ;
    USE SIGNAL ;
    PORT
      LAYER M5 ;
        RECT  92.256 189.996 92.28 190.08 ;
    END
  END f_d[276]
  PIN f_d[277]
    DIRECTION INPUT ;
    USE SIGNAL ;
    PORT
      LAYER M5 ;
        RECT  92.544 189.996 92.568 190.08 ;
    END
  END f_d[277]
  PIN f_d[278]
    DIRECTION INPUT ;
    USE SIGNAL ;
    PORT
      LAYER M5 ;
        RECT  92.832 189.996 92.856 190.08 ;
    END
  END f_d[278]
  PIN f_d[279]
    DIRECTION INPUT ;
    USE SIGNAL ;
    PORT
      LAYER M5 ;
        RECT  93.072 189.996 93.096 190.08 ;
    END
  END f_d[279]
  PIN f_d[27]
    DIRECTION INPUT ;
    USE SIGNAL ;
    PORT
      LAYER M5 ;
        RECT  21.504 189.996 21.528 190.08 ;
    END
  END f_d[27]
  PIN f_d[280]
    DIRECTION INPUT ;
    USE SIGNAL ;
    PORT
      LAYER M5 ;
        RECT  93.36 189.996 93.384 190.08 ;
    END
  END f_d[280]
  PIN f_d[281]
    DIRECTION INPUT ;
    USE SIGNAL ;
    PORT
      LAYER M5 ;
        RECT  93.648 189.996 93.672 190.08 ;
    END
  END f_d[281]
  PIN f_d[282]
    DIRECTION INPUT ;
    USE SIGNAL ;
    PORT
      LAYER M5 ;
        RECT  93.936 189.996 93.96 190.08 ;
    END
  END f_d[282]
  PIN f_d[283]
    DIRECTION INPUT ;
    USE SIGNAL ;
    PORT
      LAYER M5 ;
        RECT  94.224 189.996 94.248 190.08 ;
    END
  END f_d[283]
  PIN f_d[284]
    DIRECTION INPUT ;
    USE SIGNAL ;
    PORT
      LAYER M5 ;
        RECT  94.512 189.996 94.536 190.08 ;
    END
  END f_d[284]
  PIN f_d[285]
    DIRECTION INPUT ;
    USE SIGNAL ;
    PORT
      LAYER M5 ;
        RECT  94.8 189.996 94.824 190.08 ;
    END
  END f_d[285]
  PIN f_d[286]
    DIRECTION INPUT ;
    USE SIGNAL ;
    PORT
      LAYER M5 ;
        RECT  95.088 189.996 95.112 190.08 ;
    END
  END f_d[286]
  PIN f_d[287]
    DIRECTION INPUT ;
    USE SIGNAL ;
    PORT
      LAYER M5 ;
        RECT  95.328 189.996 95.352 190.08 ;
    END
  END f_d[287]
  PIN f_d[288]
    DIRECTION INPUT ;
    USE SIGNAL ;
    PORT
      LAYER M5 ;
        RECT  95.616 189.996 95.64 190.08 ;
    END
  END f_d[288]
  PIN f_d[289]
    DIRECTION INPUT ;
    USE SIGNAL ;
    PORT
      LAYER M5 ;
        RECT  95.904 189.996 95.928 190.08 ;
    END
  END f_d[289]
  PIN f_d[28]
    DIRECTION INPUT ;
    USE SIGNAL ;
    PORT
      LAYER M5 ;
        RECT  21.792 189.996 21.816 190.08 ;
    END
  END f_d[28]
  PIN f_d[290]
    DIRECTION INPUT ;
    USE SIGNAL ;
    PORT
      LAYER M5 ;
        RECT  96.192 189.996 96.216 190.08 ;
    END
  END f_d[290]
  PIN f_d[291]
    DIRECTION INPUT ;
    USE SIGNAL ;
    PORT
      LAYER M5 ;
        RECT  96.48 189.996 96.504 190.08 ;
    END
  END f_d[291]
  PIN f_d[292]
    DIRECTION INPUT ;
    USE SIGNAL ;
    PORT
      LAYER M5 ;
        RECT  96.768 189.996 96.792 190.08 ;
    END
  END f_d[292]
  PIN f_d[293]
    DIRECTION INPUT ;
    USE SIGNAL ;
    PORT
      LAYER M5 ;
        RECT  97.056 189.996 97.08 190.08 ;
    END
  END f_d[293]
  PIN f_d[294]
    DIRECTION INPUT ;
    USE SIGNAL ;
    PORT
      LAYER M5 ;
        RECT  97.296 189.996 97.32 190.08 ;
    END
  END f_d[294]
  PIN f_d[295]
    DIRECTION INPUT ;
    USE SIGNAL ;
    PORT
      LAYER M5 ;
        RECT  97.584 189.996 97.608 190.08 ;
    END
  END f_d[295]
  PIN f_d[296]
    DIRECTION INPUT ;
    USE SIGNAL ;
    PORT
      LAYER M5 ;
        RECT  97.872 189.996 97.896 190.08 ;
    END
  END f_d[296]
  PIN f_d[297]
    DIRECTION INPUT ;
    USE SIGNAL ;
    PORT
      LAYER M5 ;
        RECT  98.16 189.996 98.184 190.08 ;
    END
  END f_d[297]
  PIN f_d[298]
    DIRECTION INPUT ;
    USE SIGNAL ;
    PORT
      LAYER M5 ;
        RECT  98.448 189.996 98.472 190.08 ;
    END
  END f_d[298]
  PIN f_d[299]
    DIRECTION INPUT ;
    USE SIGNAL ;
    PORT
      LAYER M5 ;
        RECT  98.736 189.996 98.76 190.08 ;
    END
  END f_d[299]
  PIN f_d[29]
    DIRECTION INPUT ;
    USE SIGNAL ;
    PORT
      LAYER M5 ;
        RECT  22.08 189.996 22.104 190.08 ;
    END
  END f_d[29]
  PIN f_d[2]
    DIRECTION INPUT ;
    USE SIGNAL ;
    PORT
      LAYER M5 ;
        RECT  14.448 189.996 14.472 190.08 ;
    END
  END f_d[2]
  PIN f_d[300]
    DIRECTION INPUT ;
    USE SIGNAL ;
    PORT
      LAYER M5 ;
        RECT  99.024 189.996 99.048 190.08 ;
    END
  END f_d[300]
  PIN f_d[301]
    DIRECTION INPUT ;
    USE SIGNAL ;
    PORT
      LAYER M5 ;
        RECT  99.312 189.996 99.336 190.08 ;
    END
  END f_d[301]
  PIN f_d[302]
    DIRECTION INPUT ;
    USE SIGNAL ;
    PORT
      LAYER M5 ;
        RECT  99.552 189.996 99.576 190.08 ;
    END
  END f_d[302]
  PIN f_d[303]
    DIRECTION INPUT ;
    USE SIGNAL ;
    PORT
      LAYER M5 ;
        RECT  99.84 189.996 99.864 190.08 ;
    END
  END f_d[303]
  PIN f_d[304]
    DIRECTION INPUT ;
    USE SIGNAL ;
    PORT
      LAYER M5 ;
        RECT  100.128 189.996 100.152 190.08 ;
    END
  END f_d[304]
  PIN f_d[305]
    DIRECTION INPUT ;
    USE SIGNAL ;
    PORT
      LAYER M5 ;
        RECT  100.416 189.996 100.44 190.08 ;
    END
  END f_d[305]
  PIN f_d[306]
    DIRECTION INPUT ;
    USE SIGNAL ;
    PORT
      LAYER M5 ;
        RECT  100.704 189.996 100.728 190.08 ;
    END
  END f_d[306]
  PIN f_d[307]
    DIRECTION INPUT ;
    USE SIGNAL ;
    PORT
      LAYER M5 ;
        RECT  100.992 189.996 101.016 190.08 ;
    END
  END f_d[307]
  PIN f_d[308]
    DIRECTION INPUT ;
    USE SIGNAL ;
    PORT
      LAYER M5 ;
        RECT  101.28 189.996 101.304 190.08 ;
    END
  END f_d[308]
  PIN f_d[309]
    DIRECTION INPUT ;
    USE SIGNAL ;
    PORT
      LAYER M5 ;
        RECT  101.568 189.996 101.592 190.08 ;
    END
  END f_d[309]
  PIN f_d[30]
    DIRECTION INPUT ;
    USE SIGNAL ;
    PORT
      LAYER M5 ;
        RECT  22.368 189.996 22.392 190.08 ;
    END
  END f_d[30]
  PIN f_d[310]
    DIRECTION INPUT ;
    USE SIGNAL ;
    PORT
      LAYER M5 ;
        RECT  101.808 189.996 101.832 190.08 ;
    END
  END f_d[310]
  PIN f_d[311]
    DIRECTION INPUT ;
    USE SIGNAL ;
    PORT
      LAYER M5 ;
        RECT  102.096 189.996 102.12 190.08 ;
    END
  END f_d[311]
  PIN f_d[312]
    DIRECTION INPUT ;
    USE SIGNAL ;
    PORT
      LAYER M5 ;
        RECT  102.384 189.996 102.408 190.08 ;
    END
  END f_d[312]
  PIN f_d[313]
    DIRECTION INPUT ;
    USE SIGNAL ;
    PORT
      LAYER M5 ;
        RECT  102.672 189.996 102.696 190.08 ;
    END
  END f_d[313]
  PIN f_d[314]
    DIRECTION INPUT ;
    USE SIGNAL ;
    PORT
      LAYER M5 ;
        RECT  102.96 189.996 102.984 190.08 ;
    END
  END f_d[314]
  PIN f_d[315]
    DIRECTION INPUT ;
    USE SIGNAL ;
    PORT
      LAYER M5 ;
        RECT  103.248 189.996 103.272 190.08 ;
    END
  END f_d[315]
  PIN f_d[316]
    DIRECTION INPUT ;
    USE SIGNAL ;
    PORT
      LAYER M5 ;
        RECT  103.536 189.996 103.56 190.08 ;
    END
  END f_d[316]
  PIN f_d[317]
    DIRECTION INPUT ;
    USE SIGNAL ;
    PORT
      LAYER M5 ;
        RECT  103.824 189.996 103.848 190.08 ;
    END
  END f_d[317]
  PIN f_d[318]
    DIRECTION INPUT ;
    USE SIGNAL ;
    PORT
      LAYER M5 ;
        RECT  104.064 189.996 104.088 190.08 ;
    END
  END f_d[318]
  PIN f_d[319]
    DIRECTION INPUT ;
    USE SIGNAL ;
    PORT
      LAYER M5 ;
        RECT  104.352 189.996 104.376 190.08 ;
    END
  END f_d[319]
  PIN f_d[31]
    DIRECTION INPUT ;
    USE SIGNAL ;
    PORT
      LAYER M5 ;
        RECT  22.656 189.996 22.68 190.08 ;
    END
  END f_d[31]
  PIN f_d[320]
    DIRECTION INPUT ;
    USE SIGNAL ;
    PORT
      LAYER M5 ;
        RECT  104.64 189.996 104.664 190.08 ;
    END
  END f_d[320]
  PIN f_d[321]
    DIRECTION INPUT ;
    USE SIGNAL ;
    PORT
      LAYER M5 ;
        RECT  104.928 189.996 104.952 190.08 ;
    END
  END f_d[321]
  PIN f_d[322]
    DIRECTION INPUT ;
    USE SIGNAL ;
    PORT
      LAYER M5 ;
        RECT  105.216 189.996 105.24 190.08 ;
    END
  END f_d[322]
  PIN f_d[323]
    DIRECTION INPUT ;
    USE SIGNAL ;
    PORT
      LAYER M5 ;
        RECT  105.504 189.996 105.528 190.08 ;
    END
  END f_d[323]
  PIN f_d[324]
    DIRECTION INPUT ;
    USE SIGNAL ;
    PORT
      LAYER M5 ;
        RECT  105.792 189.996 105.816 190.08 ;
    END
  END f_d[324]
  PIN f_d[325]
    DIRECTION INPUT ;
    USE SIGNAL ;
    PORT
      LAYER M5 ;
        RECT  106.032 189.996 106.056 190.08 ;
    END
  END f_d[325]
  PIN f_d[326]
    DIRECTION INPUT ;
    USE SIGNAL ;
    PORT
      LAYER M5 ;
        RECT  106.32 189.996 106.344 190.08 ;
    END
  END f_d[326]
  PIN f_d[327]
    DIRECTION INPUT ;
    USE SIGNAL ;
    PORT
      LAYER M5 ;
        RECT  106.608 189.996 106.632 190.08 ;
    END
  END f_d[327]
  PIN f_d[328]
    DIRECTION INPUT ;
    USE SIGNAL ;
    PORT
      LAYER M5 ;
        RECT  106.896 189.996 106.92 190.08 ;
    END
  END f_d[328]
  PIN f_d[329]
    DIRECTION INPUT ;
    USE SIGNAL ;
    PORT
      LAYER M5 ;
        RECT  107.184 189.996 107.208 190.08 ;
    END
  END f_d[329]
  PIN f_d[32]
    DIRECTION INPUT ;
    USE SIGNAL ;
    PORT
      LAYER M5 ;
        RECT  22.896 189.996 22.92 190.08 ;
    END
  END f_d[32]
  PIN f_d[330]
    DIRECTION INPUT ;
    USE SIGNAL ;
    PORT
      LAYER M5 ;
        RECT  107.472 189.996 107.496 190.08 ;
    END
  END f_d[330]
  PIN f_d[331]
    DIRECTION INPUT ;
    USE SIGNAL ;
    PORT
      LAYER M5 ;
        RECT  107.76 189.996 107.784 190.08 ;
    END
  END f_d[331]
  PIN f_d[332]
    DIRECTION INPUT ;
    USE SIGNAL ;
    PORT
      LAYER M5 ;
        RECT  108.048 189.996 108.072 190.08 ;
    END
  END f_d[332]
  PIN f_d[333]
    DIRECTION INPUT ;
    USE SIGNAL ;
    PORT
      LAYER M5 ;
        RECT  108.288 189.996 108.312 190.08 ;
    END
  END f_d[333]
  PIN f_d[334]
    DIRECTION INPUT ;
    USE SIGNAL ;
    PORT
      LAYER M5 ;
        RECT  108.576 189.996 108.6 190.08 ;
    END
  END f_d[334]
  PIN f_d[335]
    DIRECTION INPUT ;
    USE SIGNAL ;
    PORT
      LAYER M5 ;
        RECT  108.864 189.996 108.888 190.08 ;
    END
  END f_d[335]
  PIN f_d[336]
    DIRECTION INPUT ;
    USE SIGNAL ;
    PORT
      LAYER M5 ;
        RECT  109.152 189.996 109.176 190.08 ;
    END
  END f_d[336]
  PIN f_d[337]
    DIRECTION INPUT ;
    USE SIGNAL ;
    PORT
      LAYER M5 ;
        RECT  109.44 189.996 109.464 190.08 ;
    END
  END f_d[337]
  PIN f_d[338]
    DIRECTION INPUT ;
    USE SIGNAL ;
    PORT
      LAYER M5 ;
        RECT  109.728 189.996 109.752 190.08 ;
    END
  END f_d[338]
  PIN f_d[339]
    DIRECTION INPUT ;
    USE SIGNAL ;
    PORT
      LAYER M5 ;
        RECT  110.016 189.996 110.04 190.08 ;
    END
  END f_d[339]
  PIN f_d[33]
    DIRECTION INPUT ;
    USE SIGNAL ;
    PORT
      LAYER M5 ;
        RECT  23.184 189.996 23.208 190.08 ;
    END
  END f_d[33]
  PIN f_d[340]
    DIRECTION INPUT ;
    USE SIGNAL ;
    PORT
      LAYER M5 ;
        RECT  110.304 189.996 110.328 190.08 ;
    END
  END f_d[340]
  PIN f_d[341]
    DIRECTION INPUT ;
    USE SIGNAL ;
    PORT
      LAYER M5 ;
        RECT  110.544 189.996 110.568 190.08 ;
    END
  END f_d[341]
  PIN f_d[342]
    DIRECTION INPUT ;
    USE SIGNAL ;
    PORT
      LAYER M5 ;
        RECT  110.832 189.996 110.856 190.08 ;
    END
  END f_d[342]
  PIN f_d[343]
    DIRECTION INPUT ;
    USE SIGNAL ;
    PORT
      LAYER M5 ;
        RECT  111.12 189.996 111.144 190.08 ;
    END
  END f_d[343]
  PIN f_d[344]
    DIRECTION INPUT ;
    USE SIGNAL ;
    PORT
      LAYER M5 ;
        RECT  111.408 189.996 111.432 190.08 ;
    END
  END f_d[344]
  PIN f_d[345]
    DIRECTION INPUT ;
    USE SIGNAL ;
    PORT
      LAYER M5 ;
        RECT  111.696 189.996 111.72 190.08 ;
    END
  END f_d[345]
  PIN f_d[346]
    DIRECTION INPUT ;
    USE SIGNAL ;
    PORT
      LAYER M5 ;
        RECT  111.984 189.996 112.008 190.08 ;
    END
  END f_d[346]
  PIN f_d[347]
    DIRECTION INPUT ;
    USE SIGNAL ;
    PORT
      LAYER M5 ;
        RECT  112.272 189.996 112.296 190.08 ;
    END
  END f_d[347]
  PIN f_d[348]
    DIRECTION INPUT ;
    USE SIGNAL ;
    PORT
      LAYER M5 ;
        RECT  112.56 189.996 112.584 190.08 ;
    END
  END f_d[348]
  PIN f_d[349]
    DIRECTION INPUT ;
    USE SIGNAL ;
    PORT
      LAYER M5 ;
        RECT  112.8 189.996 112.824 190.08 ;
    END
  END f_d[349]
  PIN f_d[34]
    DIRECTION INPUT ;
    USE SIGNAL ;
    PORT
      LAYER M5 ;
        RECT  23.472 189.996 23.496 190.08 ;
    END
  END f_d[34]
  PIN f_d[350]
    DIRECTION INPUT ;
    USE SIGNAL ;
    PORT
      LAYER M5 ;
        RECT  113.088 189.996 113.112 190.08 ;
    END
  END f_d[350]
  PIN f_d[351]
    DIRECTION INPUT ;
    USE SIGNAL ;
    PORT
      LAYER M5 ;
        RECT  113.376 189.996 113.4 190.08 ;
    END
  END f_d[351]
  PIN f_d[352]
    DIRECTION INPUT ;
    USE SIGNAL ;
    PORT
      LAYER M5 ;
        RECT  113.664 189.996 113.688 190.08 ;
    END
  END f_d[352]
  PIN f_d[353]
    DIRECTION INPUT ;
    USE SIGNAL ;
    PORT
      LAYER M5 ;
        RECT  113.952 189.996 113.976 190.08 ;
    END
  END f_d[353]
  PIN f_d[354]
    DIRECTION INPUT ;
    USE SIGNAL ;
    PORT
      LAYER M5 ;
        RECT  114.24 189.996 114.264 190.08 ;
    END
  END f_d[354]
  PIN f_d[355]
    DIRECTION INPUT ;
    USE SIGNAL ;
    PORT
      LAYER M5 ;
        RECT  114.528 189.996 114.552 190.08 ;
    END
  END f_d[355]
  PIN f_d[356]
    DIRECTION INPUT ;
    USE SIGNAL ;
    PORT
      LAYER M5 ;
        RECT  114.768 189.996 114.792 190.08 ;
    END
  END f_d[356]
  PIN f_d[357]
    DIRECTION INPUT ;
    USE SIGNAL ;
    PORT
      LAYER M5 ;
        RECT  115.056 189.996 115.08 190.08 ;
    END
  END f_d[357]
  PIN f_d[358]
    DIRECTION INPUT ;
    USE SIGNAL ;
    PORT
      LAYER M5 ;
        RECT  115.344 189.996 115.368 190.08 ;
    END
  END f_d[358]
  PIN f_d[359]
    DIRECTION INPUT ;
    USE SIGNAL ;
    PORT
      LAYER M5 ;
        RECT  115.632 189.996 115.656 190.08 ;
    END
  END f_d[359]
  PIN f_d[35]
    DIRECTION INPUT ;
    USE SIGNAL ;
    PORT
      LAYER M5 ;
        RECT  23.76 189.996 23.784 190.08 ;
    END
  END f_d[35]
  PIN f_d[360]
    DIRECTION INPUT ;
    USE SIGNAL ;
    PORT
      LAYER M5 ;
        RECT  115.92 189.996 115.944 190.08 ;
    END
  END f_d[360]
  PIN f_d[361]
    DIRECTION INPUT ;
    USE SIGNAL ;
    PORT
      LAYER M5 ;
        RECT  116.208 189.996 116.232 190.08 ;
    END
  END f_d[361]
  PIN f_d[362]
    DIRECTION INPUT ;
    USE SIGNAL ;
    PORT
      LAYER M5 ;
        RECT  116.496 189.996 116.52 190.08 ;
    END
  END f_d[362]
  PIN f_d[363]
    DIRECTION INPUT ;
    USE SIGNAL ;
    PORT
      LAYER M5 ;
        RECT  116.784 189.996 116.808 190.08 ;
    END
  END f_d[363]
  PIN f_d[364]
    DIRECTION INPUT ;
    USE SIGNAL ;
    PORT
      LAYER M5 ;
        RECT  117.024 189.996 117.048 190.08 ;
    END
  END f_d[364]
  PIN f_d[365]
    DIRECTION INPUT ;
    USE SIGNAL ;
    PORT
      LAYER M5 ;
        RECT  117.312 189.996 117.336 190.08 ;
    END
  END f_d[365]
  PIN f_d[366]
    DIRECTION INPUT ;
    USE SIGNAL ;
    PORT
      LAYER M5 ;
        RECT  117.6 189.996 117.624 190.08 ;
    END
  END f_d[366]
  PIN f_d[367]
    DIRECTION INPUT ;
    USE SIGNAL ;
    PORT
      LAYER M5 ;
        RECT  117.888 189.996 117.912 190.08 ;
    END
  END f_d[367]
  PIN f_d[368]
    DIRECTION INPUT ;
    USE SIGNAL ;
    PORT
      LAYER M5 ;
        RECT  118.176 189.996 118.2 190.08 ;
    END
  END f_d[368]
  PIN f_d[369]
    DIRECTION INPUT ;
    USE SIGNAL ;
    PORT
      LAYER M5 ;
        RECT  118.464 189.996 118.488 190.08 ;
    END
  END f_d[369]
  PIN f_d[36]
    DIRECTION INPUT ;
    USE SIGNAL ;
    PORT
      LAYER M5 ;
        RECT  24.048 189.996 24.072 190.08 ;
    END
  END f_d[36]
  PIN f_d[370]
    DIRECTION INPUT ;
    USE SIGNAL ;
    PORT
      LAYER M5 ;
        RECT  118.752 189.996 118.776 190.08 ;
    END
  END f_d[370]
  PIN f_d[371]
    DIRECTION INPUT ;
    USE SIGNAL ;
    PORT
      LAYER M5 ;
        RECT  119.04 189.996 119.064 190.08 ;
    END
  END f_d[371]
  PIN f_d[372]
    DIRECTION INPUT ;
    USE SIGNAL ;
    PORT
      LAYER M5 ;
        RECT  119.28 189.996 119.304 190.08 ;
    END
  END f_d[372]
  PIN f_d[373]
    DIRECTION INPUT ;
    USE SIGNAL ;
    PORT
      LAYER M5 ;
        RECT  119.568 189.996 119.592 190.08 ;
    END
  END f_d[373]
  PIN f_d[374]
    DIRECTION INPUT ;
    USE SIGNAL ;
    PORT
      LAYER M5 ;
        RECT  119.856 189.996 119.88 190.08 ;
    END
  END f_d[374]
  PIN f_d[375]
    DIRECTION INPUT ;
    USE SIGNAL ;
    PORT
      LAYER M5 ;
        RECT  120.144 189.996 120.168 190.08 ;
    END
  END f_d[375]
  PIN f_d[376]
    DIRECTION INPUT ;
    USE SIGNAL ;
    PORT
      LAYER M5 ;
        RECT  120.432 189.996 120.456 190.08 ;
    END
  END f_d[376]
  PIN f_d[377]
    DIRECTION INPUT ;
    USE SIGNAL ;
    PORT
      LAYER M5 ;
        RECT  120.72 189.996 120.744 190.08 ;
    END
  END f_d[377]
  PIN f_d[378]
    DIRECTION INPUT ;
    USE SIGNAL ;
    PORT
      LAYER M5 ;
        RECT  121.008 189.996 121.032 190.08 ;
    END
  END f_d[378]
  PIN f_d[379]
    DIRECTION INPUT ;
    USE SIGNAL ;
    PORT
      LAYER M5 ;
        RECT  121.296 189.996 121.32 190.08 ;
    END
  END f_d[379]
  PIN f_d[37]
    DIRECTION INPUT ;
    USE SIGNAL ;
    PORT
      LAYER M5 ;
        RECT  24.336 189.996 24.36 190.08 ;
    END
  END f_d[37]
  PIN f_d[380]
    DIRECTION INPUT ;
    USE SIGNAL ;
    PORT
      LAYER M5 ;
        RECT  121.536 189.996 121.56 190.08 ;
    END
  END f_d[380]
  PIN f_d[381]
    DIRECTION INPUT ;
    USE SIGNAL ;
    PORT
      LAYER M5 ;
        RECT  121.824 189.996 121.848 190.08 ;
    END
  END f_d[381]
  PIN f_d[382]
    DIRECTION INPUT ;
    USE SIGNAL ;
    PORT
      LAYER M5 ;
        RECT  122.112 189.996 122.136 190.08 ;
    END
  END f_d[382]
  PIN f_d[383]
    DIRECTION INPUT ;
    USE SIGNAL ;
    PORT
      LAYER M5 ;
        RECT  122.4 189.996 122.424 190.08 ;
    END
  END f_d[383]
  PIN f_d[384]
    DIRECTION INPUT ;
    USE SIGNAL ;
    PORT
      LAYER M5 ;
        RECT  122.688 189.996 122.712 190.08 ;
    END
  END f_d[384]
  PIN f_d[385]
    DIRECTION INPUT ;
    USE SIGNAL ;
    PORT
      LAYER M5 ;
        RECT  122.976 189.996 123 190.08 ;
    END
  END f_d[385]
  PIN f_d[386]
    DIRECTION INPUT ;
    USE SIGNAL ;
    PORT
      LAYER M5 ;
        RECT  123.264 189.996 123.288 190.08 ;
    END
  END f_d[386]
  PIN f_d[387]
    DIRECTION INPUT ;
    USE SIGNAL ;
    PORT
      LAYER M5 ;
        RECT  123.504 189.996 123.528 190.08 ;
    END
  END f_d[387]
  PIN f_d[388]
    DIRECTION INPUT ;
    USE SIGNAL ;
    PORT
      LAYER M5 ;
        RECT  123.792 189.996 123.816 190.08 ;
    END
  END f_d[388]
  PIN f_d[389]
    DIRECTION INPUT ;
    USE SIGNAL ;
    PORT
      LAYER M5 ;
        RECT  124.08 189.996 124.104 190.08 ;
    END
  END f_d[389]
  PIN f_d[38]
    DIRECTION INPUT ;
    USE SIGNAL ;
    PORT
      LAYER M5 ;
        RECT  24.624 189.996 24.648 190.08 ;
    END
  END f_d[38]
  PIN f_d[390]
    DIRECTION INPUT ;
    USE SIGNAL ;
    PORT
      LAYER M5 ;
        RECT  124.368 189.996 124.392 190.08 ;
    END
  END f_d[390]
  PIN f_d[391]
    DIRECTION INPUT ;
    USE SIGNAL ;
    PORT
      LAYER M5 ;
        RECT  124.656 189.996 124.68 190.08 ;
    END
  END f_d[391]
  PIN f_d[392]
    DIRECTION INPUT ;
    USE SIGNAL ;
    PORT
      LAYER M5 ;
        RECT  124.944 189.996 124.968 190.08 ;
    END
  END f_d[392]
  PIN f_d[393]
    DIRECTION INPUT ;
    USE SIGNAL ;
    PORT
      LAYER M5 ;
        RECT  125.232 189.996 125.256 190.08 ;
    END
  END f_d[393]
  PIN f_d[394]
    DIRECTION INPUT ;
    USE SIGNAL ;
    PORT
      LAYER M5 ;
        RECT  125.52 189.996 125.544 190.08 ;
    END
  END f_d[394]
  PIN f_d[395]
    DIRECTION INPUT ;
    USE SIGNAL ;
    PORT
      LAYER M5 ;
        RECT  125.76 189.996 125.784 190.08 ;
    END
  END f_d[395]
  PIN f_d[396]
    DIRECTION INPUT ;
    USE SIGNAL ;
    PORT
      LAYER M5 ;
        RECT  126.048 189.996 126.072 190.08 ;
    END
  END f_d[396]
  PIN f_d[397]
    DIRECTION INPUT ;
    USE SIGNAL ;
    PORT
      LAYER M5 ;
        RECT  126.336 189.996 126.36 190.08 ;
    END
  END f_d[397]
  PIN f_d[398]
    DIRECTION INPUT ;
    USE SIGNAL ;
    PORT
      LAYER M5 ;
        RECT  126.624 189.996 126.648 190.08 ;
    END
  END f_d[398]
  PIN f_d[399]
    DIRECTION INPUT ;
    USE SIGNAL ;
    PORT
      LAYER M5 ;
        RECT  126.912 189.996 126.936 190.08 ;
    END
  END f_d[399]
  PIN f_d[39]
    DIRECTION INPUT ;
    USE SIGNAL ;
    PORT
      LAYER M5 ;
        RECT  24.912 189.996 24.936 190.08 ;
    END
  END f_d[39]
  PIN f_d[3]
    DIRECTION INPUT ;
    USE SIGNAL ;
    PORT
      LAYER M5 ;
        RECT  14.736 189.996 14.76 190.08 ;
    END
  END f_d[3]
  PIN f_d[400]
    DIRECTION INPUT ;
    USE SIGNAL ;
    PORT
      LAYER M5 ;
        RECT  127.2 189.996 127.224 190.08 ;
    END
  END f_d[400]
  PIN f_d[401]
    DIRECTION INPUT ;
    USE SIGNAL ;
    PORT
      LAYER M5 ;
        RECT  127.488 189.996 127.512 190.08 ;
    END
  END f_d[401]
  PIN f_d[402]
    DIRECTION INPUT ;
    USE SIGNAL ;
    PORT
      LAYER M5 ;
        RECT  127.776 189.996 127.8 190.08 ;
    END
  END f_d[402]
  PIN f_d[403]
    DIRECTION INPUT ;
    USE SIGNAL ;
    PORT
      LAYER M5 ;
        RECT  128.016 189.996 128.04 190.08 ;
    END
  END f_d[403]
  PIN f_d[404]
    DIRECTION INPUT ;
    USE SIGNAL ;
    PORT
      LAYER M5 ;
        RECT  128.304 189.996 128.328 190.08 ;
    END
  END f_d[404]
  PIN f_d[405]
    DIRECTION INPUT ;
    USE SIGNAL ;
    PORT
      LAYER M5 ;
        RECT  128.592 189.996 128.616 190.08 ;
    END
  END f_d[405]
  PIN f_d[406]
    DIRECTION INPUT ;
    USE SIGNAL ;
    PORT
      LAYER M5 ;
        RECT  128.88 189.996 128.904 190.08 ;
    END
  END f_d[406]
  PIN f_d[407]
    DIRECTION INPUT ;
    USE SIGNAL ;
    PORT
      LAYER M5 ;
        RECT  129.168 189.996 129.192 190.08 ;
    END
  END f_d[407]
  PIN f_d[408]
    DIRECTION INPUT ;
    USE SIGNAL ;
    PORT
      LAYER M5 ;
        RECT  129.456 189.996 129.48 190.08 ;
    END
  END f_d[408]
  PIN f_d[409]
    DIRECTION INPUT ;
    USE SIGNAL ;
    PORT
      LAYER M5 ;
        RECT  129.744 189.996 129.768 190.08 ;
    END
  END f_d[409]
  PIN f_d[40]
    DIRECTION INPUT ;
    USE SIGNAL ;
    PORT
      LAYER M5 ;
        RECT  25.152 189.996 25.176 190.08 ;
    END
  END f_d[40]
  PIN f_d[410]
    DIRECTION INPUT ;
    USE SIGNAL ;
    PORT
      LAYER M5 ;
        RECT  130.032 189.996 130.056 190.08 ;
    END
  END f_d[410]
  PIN f_d[411]
    DIRECTION INPUT ;
    USE SIGNAL ;
    PORT
      LAYER M5 ;
        RECT  130.272 189.996 130.296 190.08 ;
    END
  END f_d[411]
  PIN f_d[412]
    DIRECTION INPUT ;
    USE SIGNAL ;
    PORT
      LAYER M5 ;
        RECT  130.56 189.996 130.584 190.08 ;
    END
  END f_d[412]
  PIN f_d[413]
    DIRECTION INPUT ;
    USE SIGNAL ;
    PORT
      LAYER M5 ;
        RECT  130.848 189.996 130.872 190.08 ;
    END
  END f_d[413]
  PIN f_d[414]
    DIRECTION INPUT ;
    USE SIGNAL ;
    PORT
      LAYER M5 ;
        RECT  131.136 189.996 131.16 190.08 ;
    END
  END f_d[414]
  PIN f_d[415]
    DIRECTION INPUT ;
    USE SIGNAL ;
    PORT
      LAYER M5 ;
        RECT  131.424 189.996 131.448 190.08 ;
    END
  END f_d[415]
  PIN f_d[416]
    DIRECTION INPUT ;
    USE SIGNAL ;
    PORT
      LAYER M5 ;
        RECT  131.712 189.996 131.736 190.08 ;
    END
  END f_d[416]
  PIN f_d[417]
    DIRECTION INPUT ;
    USE SIGNAL ;
    PORT
      LAYER M5 ;
        RECT  132 189.996 132.024 190.08 ;
    END
  END f_d[417]
  PIN f_d[418]
    DIRECTION INPUT ;
    USE SIGNAL ;
    PORT
      LAYER M5 ;
        RECT  132.24 189.996 132.264 190.08 ;
    END
  END f_d[418]
  PIN f_d[419]
    DIRECTION INPUT ;
    USE SIGNAL ;
    PORT
      LAYER M5 ;
        RECT  132.528 189.996 132.552 190.08 ;
    END
  END f_d[419]
  PIN f_d[41]
    DIRECTION INPUT ;
    USE SIGNAL ;
    PORT
      LAYER M5 ;
        RECT  25.44 189.996 25.464 190.08 ;
    END
  END f_d[41]
  PIN f_d[420]
    DIRECTION INPUT ;
    USE SIGNAL ;
    PORT
      LAYER M5 ;
        RECT  132.816 189.996 132.84 190.08 ;
    END
  END f_d[420]
  PIN f_d[421]
    DIRECTION INPUT ;
    USE SIGNAL ;
    PORT
      LAYER M5 ;
        RECT  133.104 189.996 133.128 190.08 ;
    END
  END f_d[421]
  PIN f_d[422]
    DIRECTION INPUT ;
    USE SIGNAL ;
    PORT
      LAYER M5 ;
        RECT  133.392 189.996 133.416 190.08 ;
    END
  END f_d[422]
  PIN f_d[423]
    DIRECTION INPUT ;
    USE SIGNAL ;
    PORT
      LAYER M5 ;
        RECT  133.68 189.996 133.704 190.08 ;
    END
  END f_d[423]
  PIN f_d[424]
    DIRECTION INPUT ;
    USE SIGNAL ;
    PORT
      LAYER M5 ;
        RECT  133.968 189.996 133.992 190.08 ;
    END
  END f_d[424]
  PIN f_d[425]
    DIRECTION INPUT ;
    USE SIGNAL ;
    PORT
      LAYER M5 ;
        RECT  134.256 189.996 134.28 190.08 ;
    END
  END f_d[425]
  PIN f_d[426]
    DIRECTION INPUT ;
    USE SIGNAL ;
    PORT
      LAYER M5 ;
        RECT  134.496 189.996 134.52 190.08 ;
    END
  END f_d[426]
  PIN f_d[427]
    DIRECTION INPUT ;
    USE SIGNAL ;
    PORT
      LAYER M5 ;
        RECT  134.784 189.996 134.808 190.08 ;
    END
  END f_d[427]
  PIN f_d[428]
    DIRECTION INPUT ;
    USE SIGNAL ;
    PORT
      LAYER M5 ;
        RECT  135.072 189.996 135.096 190.08 ;
    END
  END f_d[428]
  PIN f_d[429]
    DIRECTION INPUT ;
    USE SIGNAL ;
    PORT
      LAYER M5 ;
        RECT  135.36 189.996 135.384 190.08 ;
    END
  END f_d[429]
  PIN f_d[42]
    DIRECTION INPUT ;
    USE SIGNAL ;
    PORT
      LAYER M5 ;
        RECT  25.728 189.996 25.752 190.08 ;
    END
  END f_d[42]
  PIN f_d[430]
    DIRECTION INPUT ;
    USE SIGNAL ;
    PORT
      LAYER M5 ;
        RECT  135.648 189.996 135.672 190.08 ;
    END
  END f_d[430]
  PIN f_d[431]
    DIRECTION INPUT ;
    USE SIGNAL ;
    PORT
      LAYER M5 ;
        RECT  135.936 189.996 135.96 190.08 ;
    END
  END f_d[431]
  PIN f_d[432]
    DIRECTION INPUT ;
    USE SIGNAL ;
    PORT
      LAYER M5 ;
        RECT  136.224 189.996 136.248 190.08 ;
    END
  END f_d[432]
  PIN f_d[433]
    DIRECTION INPUT ;
    USE SIGNAL ;
    PORT
      LAYER M5 ;
        RECT  136.512 189.996 136.536 190.08 ;
    END
  END f_d[433]
  PIN f_d[434]
    DIRECTION INPUT ;
    USE SIGNAL ;
    PORT
      LAYER M5 ;
        RECT  136.752 189.996 136.776 190.08 ;
    END
  END f_d[434]
  PIN f_d[435]
    DIRECTION INPUT ;
    USE SIGNAL ;
    PORT
      LAYER M5 ;
        RECT  137.04 189.996 137.064 190.08 ;
    END
  END f_d[435]
  PIN f_d[436]
    DIRECTION INPUT ;
    USE SIGNAL ;
    PORT
      LAYER M5 ;
        RECT  137.328 189.996 137.352 190.08 ;
    END
  END f_d[436]
  PIN f_d[437]
    DIRECTION INPUT ;
    USE SIGNAL ;
    PORT
      LAYER M5 ;
        RECT  137.616 189.996 137.64 190.08 ;
    END
  END f_d[437]
  PIN f_d[438]
    DIRECTION INPUT ;
    USE SIGNAL ;
    PORT
      LAYER M5 ;
        RECT  137.904 189.996 137.928 190.08 ;
    END
  END f_d[438]
  PIN f_d[439]
    DIRECTION INPUT ;
    USE SIGNAL ;
    PORT
      LAYER M5 ;
        RECT  138.192 189.996 138.216 190.08 ;
    END
  END f_d[439]
  PIN f_d[43]
    DIRECTION INPUT ;
    USE SIGNAL ;
    PORT
      LAYER M5 ;
        RECT  26.016 189.996 26.04 190.08 ;
    END
  END f_d[43]
  PIN f_d[440]
    DIRECTION INPUT ;
    USE SIGNAL ;
    PORT
      LAYER M5 ;
        RECT  138.48 189.996 138.504 190.08 ;
    END
  END f_d[440]
  PIN f_d[441]
    DIRECTION INPUT ;
    USE SIGNAL ;
    PORT
      LAYER M5 ;
        RECT  138.768 189.996 138.792 190.08 ;
    END
  END f_d[441]
  PIN f_d[442]
    DIRECTION INPUT ;
    USE SIGNAL ;
    PORT
      LAYER M5 ;
        RECT  139.008 189.996 139.032 190.08 ;
    END
  END f_d[442]
  PIN f_d[443]
    DIRECTION INPUT ;
    USE SIGNAL ;
    PORT
      LAYER M5 ;
        RECT  139.296 189.996 139.32 190.08 ;
    END
  END f_d[443]
  PIN f_d[444]
    DIRECTION INPUT ;
    USE SIGNAL ;
    PORT
      LAYER M5 ;
        RECT  139.584 189.996 139.608 190.08 ;
    END
  END f_d[444]
  PIN f_d[445]
    DIRECTION INPUT ;
    USE SIGNAL ;
    PORT
      LAYER M5 ;
        RECT  139.872 189.996 139.896 190.08 ;
    END
  END f_d[445]
  PIN f_d[446]
    DIRECTION INPUT ;
    USE SIGNAL ;
    PORT
      LAYER M5 ;
        RECT  140.16 189.996 140.184 190.08 ;
    END
  END f_d[446]
  PIN f_d[447]
    DIRECTION INPUT ;
    USE SIGNAL ;
    PORT
      LAYER M5 ;
        RECT  140.448 189.996 140.472 190.08 ;
    END
  END f_d[447]
  PIN f_d[448]
    DIRECTION INPUT ;
    USE SIGNAL ;
    PORT
      LAYER M5 ;
        RECT  140.736 189.996 140.76 190.08 ;
    END
  END f_d[448]
  PIN f_d[449]
    DIRECTION INPUT ;
    USE SIGNAL ;
    PORT
      LAYER M5 ;
        RECT  140.976 189.996 141 190.08 ;
    END
  END f_d[449]
  PIN f_d[44]
    DIRECTION INPUT ;
    USE SIGNAL ;
    PORT
      LAYER M5 ;
        RECT  26.304 189.996 26.328 190.08 ;
    END
  END f_d[44]
  PIN f_d[450]
    DIRECTION INPUT ;
    USE SIGNAL ;
    PORT
      LAYER M5 ;
        RECT  141.264 189.996 141.288 190.08 ;
    END
  END f_d[450]
  PIN f_d[451]
    DIRECTION INPUT ;
    USE SIGNAL ;
    PORT
      LAYER M5 ;
        RECT  141.552 189.996 141.576 190.08 ;
    END
  END f_d[451]
  PIN f_d[452]
    DIRECTION INPUT ;
    USE SIGNAL ;
    PORT
      LAYER M5 ;
        RECT  141.84 189.996 141.864 190.08 ;
    END
  END f_d[452]
  PIN f_d[453]
    DIRECTION INPUT ;
    USE SIGNAL ;
    PORT
      LAYER M5 ;
        RECT  142.128 189.996 142.152 190.08 ;
    END
  END f_d[453]
  PIN f_d[454]
    DIRECTION INPUT ;
    USE SIGNAL ;
    PORT
      LAYER M5 ;
        RECT  142.416 189.996 142.44 190.08 ;
    END
  END f_d[454]
  PIN f_d[455]
    DIRECTION INPUT ;
    USE SIGNAL ;
    PORT
      LAYER M5 ;
        RECT  142.704 189.996 142.728 190.08 ;
    END
  END f_d[455]
  PIN f_d[456]
    DIRECTION INPUT ;
    USE SIGNAL ;
    PORT
      LAYER M5 ;
        RECT  142.992 189.996 143.016 190.08 ;
    END
  END f_d[456]
  PIN f_d[457]
    DIRECTION INPUT ;
    USE SIGNAL ;
    PORT
      LAYER M5 ;
        RECT  143.232 189.996 143.256 190.08 ;
    END
  END f_d[457]
  PIN f_d[458]
    DIRECTION INPUT ;
    USE SIGNAL ;
    PORT
      LAYER M5 ;
        RECT  143.52 189.996 143.544 190.08 ;
    END
  END f_d[458]
  PIN f_d[459]
    DIRECTION INPUT ;
    USE SIGNAL ;
    PORT
      LAYER M5 ;
        RECT  143.808 189.996 143.832 190.08 ;
    END
  END f_d[459]
  PIN f_d[45]
    DIRECTION INPUT ;
    USE SIGNAL ;
    PORT
      LAYER M5 ;
        RECT  26.592 189.996 26.616 190.08 ;
    END
  END f_d[45]
  PIN f_d[460]
    DIRECTION INPUT ;
    USE SIGNAL ;
    PORT
      LAYER M5 ;
        RECT  144.096 189.996 144.12 190.08 ;
    END
  END f_d[460]
  PIN f_d[461]
    DIRECTION INPUT ;
    USE SIGNAL ;
    PORT
      LAYER M5 ;
        RECT  144.384 189.996 144.408 190.08 ;
    END
  END f_d[461]
  PIN f_d[462]
    DIRECTION INPUT ;
    USE SIGNAL ;
    PORT
      LAYER M5 ;
        RECT  144.672 189.996 144.696 190.08 ;
    END
  END f_d[462]
  PIN f_d[463]
    DIRECTION INPUT ;
    USE SIGNAL ;
    PORT
      LAYER M5 ;
        RECT  144.96 189.996 144.984 190.08 ;
    END
  END f_d[463]
  PIN f_d[464]
    DIRECTION INPUT ;
    USE SIGNAL ;
    PORT
      LAYER M5 ;
        RECT  145.248 189.996 145.272 190.08 ;
    END
  END f_d[464]
  PIN f_d[465]
    DIRECTION INPUT ;
    USE SIGNAL ;
    PORT
      LAYER M5 ;
        RECT  145.488 189.996 145.512 190.08 ;
    END
  END f_d[465]
  PIN f_d[466]
    DIRECTION INPUT ;
    USE SIGNAL ;
    PORT
      LAYER M5 ;
        RECT  145.776 189.996 145.8 190.08 ;
    END
  END f_d[466]
  PIN f_d[467]
    DIRECTION INPUT ;
    USE SIGNAL ;
    PORT
      LAYER M5 ;
        RECT  146.064 189.996 146.088 190.08 ;
    END
  END f_d[467]
  PIN f_d[468]
    DIRECTION INPUT ;
    USE SIGNAL ;
    PORT
      LAYER M5 ;
        RECT  146.352 189.996 146.376 190.08 ;
    END
  END f_d[468]
  PIN f_d[469]
    DIRECTION INPUT ;
    USE SIGNAL ;
    PORT
      LAYER M5 ;
        RECT  146.64 189.996 146.664 190.08 ;
    END
  END f_d[469]
  PIN f_d[46]
    DIRECTION INPUT ;
    USE SIGNAL ;
    PORT
      LAYER M5 ;
        RECT  26.88 189.996 26.904 190.08 ;
    END
  END f_d[46]
  PIN f_d[470]
    DIRECTION INPUT ;
    USE SIGNAL ;
    PORT
      LAYER M5 ;
        RECT  146.928 189.996 146.952 190.08 ;
    END
  END f_d[470]
  PIN f_d[471]
    DIRECTION INPUT ;
    USE SIGNAL ;
    PORT
      LAYER M5 ;
        RECT  147.216 189.996 147.24 190.08 ;
    END
  END f_d[471]
  PIN f_d[472]
    DIRECTION INPUT ;
    USE SIGNAL ;
    PORT
      LAYER M5 ;
        RECT  147.504 189.996 147.528 190.08 ;
    END
  END f_d[472]
  PIN f_d[473]
    DIRECTION INPUT ;
    USE SIGNAL ;
    PORT
      LAYER M5 ;
        RECT  147.744 189.996 147.768 190.08 ;
    END
  END f_d[473]
  PIN f_d[474]
    DIRECTION INPUT ;
    USE SIGNAL ;
    PORT
      LAYER M5 ;
        RECT  148.032 189.996 148.056 190.08 ;
    END
  END f_d[474]
  PIN f_d[475]
    DIRECTION INPUT ;
    USE SIGNAL ;
    PORT
      LAYER M5 ;
        RECT  148.32 189.996 148.344 190.08 ;
    END
  END f_d[475]
  PIN f_d[476]
    DIRECTION INPUT ;
    USE SIGNAL ;
    PORT
      LAYER M5 ;
        RECT  148.608 189.996 148.632 190.08 ;
    END
  END f_d[476]
  PIN f_d[477]
    DIRECTION INPUT ;
    USE SIGNAL ;
    PORT
      LAYER M5 ;
        RECT  148.896 189.996 148.92 190.08 ;
    END
  END f_d[477]
  PIN f_d[478]
    DIRECTION INPUT ;
    USE SIGNAL ;
    PORT
      LAYER M5 ;
        RECT  149.184 189.996 149.208 190.08 ;
    END
  END f_d[478]
  PIN f_d[479]
    DIRECTION INPUT ;
    USE SIGNAL ;
    PORT
      LAYER M5 ;
        RECT  149.472 189.996 149.496 190.08 ;
    END
  END f_d[479]
  PIN f_d[47]
    DIRECTION INPUT ;
    USE SIGNAL ;
    PORT
      LAYER M5 ;
        RECT  27.168 189.996 27.192 190.08 ;
    END
  END f_d[47]
  PIN f_d[48]
    DIRECTION INPUT ;
    USE SIGNAL ;
    PORT
      LAYER M5 ;
        RECT  27.408 189.996 27.432 190.08 ;
    END
  END f_d[48]
  PIN f_d[49]
    DIRECTION INPUT ;
    USE SIGNAL ;
    PORT
      LAYER M5 ;
        RECT  27.696 189.996 27.72 190.08 ;
    END
  END f_d[49]
  PIN f_d[4]
    DIRECTION INPUT ;
    USE SIGNAL ;
    PORT
      LAYER M5 ;
        RECT  15.024 189.996 15.048 190.08 ;
    END
  END f_d[4]
  PIN f_d[50]
    DIRECTION INPUT ;
    USE SIGNAL ;
    PORT
      LAYER M5 ;
        RECT  27.984 189.996 28.008 190.08 ;
    END
  END f_d[50]
  PIN f_d[51]
    DIRECTION INPUT ;
    USE SIGNAL ;
    PORT
      LAYER M5 ;
        RECT  28.272 189.996 28.296 190.08 ;
    END
  END f_d[51]
  PIN f_d[52]
    DIRECTION INPUT ;
    USE SIGNAL ;
    PORT
      LAYER M5 ;
        RECT  28.56 189.996 28.584 190.08 ;
    END
  END f_d[52]
  PIN f_d[53]
    DIRECTION INPUT ;
    USE SIGNAL ;
    PORT
      LAYER M5 ;
        RECT  28.848 189.996 28.872 190.08 ;
    END
  END f_d[53]
  PIN f_d[54]
    DIRECTION INPUT ;
    USE SIGNAL ;
    PORT
      LAYER M5 ;
        RECT  29.136 189.996 29.16 190.08 ;
    END
  END f_d[54]
  PIN f_d[55]
    DIRECTION INPUT ;
    USE SIGNAL ;
    PORT
      LAYER M5 ;
        RECT  29.424 189.996 29.448 190.08 ;
    END
  END f_d[55]
  PIN f_d[56]
    DIRECTION INPUT ;
    USE SIGNAL ;
    PORT
      LAYER M5 ;
        RECT  29.664 189.996 29.688 190.08 ;
    END
  END f_d[56]
  PIN f_d[57]
    DIRECTION INPUT ;
    USE SIGNAL ;
    PORT
      LAYER M5 ;
        RECT  29.952 189.996 29.976 190.08 ;
    END
  END f_d[57]
  PIN f_d[58]
    DIRECTION INPUT ;
    USE SIGNAL ;
    PORT
      LAYER M5 ;
        RECT  30.24 189.996 30.264 190.08 ;
    END
  END f_d[58]
  PIN f_d[59]
    DIRECTION INPUT ;
    USE SIGNAL ;
    PORT
      LAYER M5 ;
        RECT  30.528 189.996 30.552 190.08 ;
    END
  END f_d[59]
  PIN f_d[5]
    DIRECTION INPUT ;
    USE SIGNAL ;
    PORT
      LAYER M5 ;
        RECT  15.312 189.996 15.336 190.08 ;
    END
  END f_d[5]
  PIN f_d[60]
    DIRECTION INPUT ;
    USE SIGNAL ;
    PORT
      LAYER M5 ;
        RECT  30.816 189.996 30.84 190.08 ;
    END
  END f_d[60]
  PIN f_d[61]
    DIRECTION INPUT ;
    USE SIGNAL ;
    PORT
      LAYER M5 ;
        RECT  31.104 189.996 31.128 190.08 ;
    END
  END f_d[61]
  PIN f_d[62]
    DIRECTION INPUT ;
    USE SIGNAL ;
    PORT
      LAYER M5 ;
        RECT  31.392 189.996 31.416 190.08 ;
    END
  END f_d[62]
  PIN f_d[63]
    DIRECTION INPUT ;
    USE SIGNAL ;
    PORT
      LAYER M5 ;
        RECT  31.632 189.996 31.656 190.08 ;
    END
  END f_d[63]
  PIN f_d[64]
    DIRECTION INPUT ;
    USE SIGNAL ;
    PORT
      LAYER M5 ;
        RECT  31.92 189.996 31.944 190.08 ;
    END
  END f_d[64]
  PIN f_d[65]
    DIRECTION INPUT ;
    USE SIGNAL ;
    PORT
      LAYER M5 ;
        RECT  32.208 189.996 32.232 190.08 ;
    END
  END f_d[65]
  PIN f_d[66]
    DIRECTION INPUT ;
    USE SIGNAL ;
    PORT
      LAYER M5 ;
        RECT  32.496 189.996 32.52 190.08 ;
    END
  END f_d[66]
  PIN f_d[67]
    DIRECTION INPUT ;
    USE SIGNAL ;
    PORT
      LAYER M5 ;
        RECT  32.784 189.996 32.808 190.08 ;
    END
  END f_d[67]
  PIN f_d[68]
    DIRECTION INPUT ;
    USE SIGNAL ;
    PORT
      LAYER M5 ;
        RECT  33.072 189.996 33.096 190.08 ;
    END
  END f_d[68]
  PIN f_d[69]
    DIRECTION INPUT ;
    USE SIGNAL ;
    PORT
      LAYER M5 ;
        RECT  33.36 189.996 33.384 190.08 ;
    END
  END f_d[69]
  PIN f_d[6]
    DIRECTION INPUT ;
    USE SIGNAL ;
    PORT
      LAYER M5 ;
        RECT  15.6 189.996 15.624 190.08 ;
    END
  END f_d[6]
  PIN f_d[70]
    DIRECTION INPUT ;
    USE SIGNAL ;
    PORT
      LAYER M5 ;
        RECT  33.648 189.996 33.672 190.08 ;
    END
  END f_d[70]
  PIN f_d[71]
    DIRECTION INPUT ;
    USE SIGNAL ;
    PORT
      LAYER M5 ;
        RECT  33.888 189.996 33.912 190.08 ;
    END
  END f_d[71]
  PIN f_d[72]
    DIRECTION INPUT ;
    USE SIGNAL ;
    PORT
      LAYER M5 ;
        RECT  34.176 189.996 34.2 190.08 ;
    END
  END f_d[72]
  PIN f_d[73]
    DIRECTION INPUT ;
    USE SIGNAL ;
    PORT
      LAYER M5 ;
        RECT  34.464 189.996 34.488 190.08 ;
    END
  END f_d[73]
  PIN f_d[74]
    DIRECTION INPUT ;
    USE SIGNAL ;
    PORT
      LAYER M5 ;
        RECT  34.752 189.996 34.776 190.08 ;
    END
  END f_d[74]
  PIN f_d[75]
    DIRECTION INPUT ;
    USE SIGNAL ;
    PORT
      LAYER M5 ;
        RECT  35.04 189.996 35.064 190.08 ;
    END
  END f_d[75]
  PIN f_d[76]
    DIRECTION INPUT ;
    USE SIGNAL ;
    PORT
      LAYER M5 ;
        RECT  35.328 189.996 35.352 190.08 ;
    END
  END f_d[76]
  PIN f_d[77]
    DIRECTION INPUT ;
    USE SIGNAL ;
    PORT
      LAYER M5 ;
        RECT  35.616 189.996 35.64 190.08 ;
    END
  END f_d[77]
  PIN f_d[78]
    DIRECTION INPUT ;
    USE SIGNAL ;
    PORT
      LAYER M5 ;
        RECT  35.904 189.996 35.928 190.08 ;
    END
  END f_d[78]
  PIN f_d[79]
    DIRECTION INPUT ;
    USE SIGNAL ;
    PORT
      LAYER M5 ;
        RECT  36.144 189.996 36.168 190.08 ;
    END
  END f_d[79]
  PIN f_d[7]
    DIRECTION INPUT ;
    USE SIGNAL ;
    PORT
      LAYER M5 ;
        RECT  15.888 189.996 15.912 190.08 ;
    END
  END f_d[7]
  PIN f_d[80]
    DIRECTION INPUT ;
    USE SIGNAL ;
    PORT
      LAYER M5 ;
        RECT  36.432 189.996 36.456 190.08 ;
    END
  END f_d[80]
  PIN f_d[81]
    DIRECTION INPUT ;
    USE SIGNAL ;
    PORT
      LAYER M5 ;
        RECT  36.72 189.996 36.744 190.08 ;
    END
  END f_d[81]
  PIN f_d[82]
    DIRECTION INPUT ;
    USE SIGNAL ;
    PORT
      LAYER M5 ;
        RECT  37.008 189.996 37.032 190.08 ;
    END
  END f_d[82]
  PIN f_d[83]
    DIRECTION INPUT ;
    USE SIGNAL ;
    PORT
      LAYER M5 ;
        RECT  37.296 189.996 37.32 190.08 ;
    END
  END f_d[83]
  PIN f_d[84]
    DIRECTION INPUT ;
    USE SIGNAL ;
    PORT
      LAYER M5 ;
        RECT  37.584 189.996 37.608 190.08 ;
    END
  END f_d[84]
  PIN f_d[85]
    DIRECTION INPUT ;
    USE SIGNAL ;
    PORT
      LAYER M5 ;
        RECT  37.872 189.996 37.896 190.08 ;
    END
  END f_d[85]
  PIN f_d[86]
    DIRECTION INPUT ;
    USE SIGNAL ;
    PORT
      LAYER M5 ;
        RECT  38.16 189.996 38.184 190.08 ;
    END
  END f_d[86]
  PIN f_d[87]
    DIRECTION INPUT ;
    USE SIGNAL ;
    PORT
      LAYER M5 ;
        RECT  38.4 189.996 38.424 190.08 ;
    END
  END f_d[87]
  PIN f_d[88]
    DIRECTION INPUT ;
    USE SIGNAL ;
    PORT
      LAYER M5 ;
        RECT  38.688 189.996 38.712 190.08 ;
    END
  END f_d[88]
  PIN f_d[89]
    DIRECTION INPUT ;
    USE SIGNAL ;
    PORT
      LAYER M5 ;
        RECT  38.976 189.996 39 190.08 ;
    END
  END f_d[89]
  PIN f_d[8]
    DIRECTION INPUT ;
    USE SIGNAL ;
    PORT
      LAYER M5 ;
        RECT  16.176 189.996 16.2 190.08 ;
    END
  END f_d[8]
  PIN f_d[90]
    DIRECTION INPUT ;
    USE SIGNAL ;
    PORT
      LAYER M5 ;
        RECT  39.264 189.996 39.288 190.08 ;
    END
  END f_d[90]
  PIN f_d[91]
    DIRECTION INPUT ;
    USE SIGNAL ;
    PORT
      LAYER M5 ;
        RECT  39.552 189.996 39.576 190.08 ;
    END
  END f_d[91]
  PIN f_d[92]
    DIRECTION INPUT ;
    USE SIGNAL ;
    PORT
      LAYER M5 ;
        RECT  39.84 189.996 39.864 190.08 ;
    END
  END f_d[92]
  PIN f_d[93]
    DIRECTION INPUT ;
    USE SIGNAL ;
    PORT
      LAYER M5 ;
        RECT  40.128 189.996 40.152 190.08 ;
    END
  END f_d[93]
  PIN f_d[94]
    DIRECTION INPUT ;
    USE SIGNAL ;
    PORT
      LAYER M5 ;
        RECT  40.416 189.996 40.44 190.08 ;
    END
  END f_d[94]
  PIN f_d[95]
    DIRECTION INPUT ;
    USE SIGNAL ;
    PORT
      LAYER M5 ;
        RECT  40.656 189.996 40.68 190.08 ;
    END
  END f_d[95]
  PIN f_d[96]
    DIRECTION INPUT ;
    USE SIGNAL ;
    PORT
      LAYER M5 ;
        RECT  40.944 189.996 40.968 190.08 ;
    END
  END f_d[96]
  PIN f_d[97]
    DIRECTION INPUT ;
    USE SIGNAL ;
    PORT
      LAYER M5 ;
        RECT  41.232 189.996 41.256 190.08 ;
    END
  END f_d[97]
  PIN f_d[98]
    DIRECTION INPUT ;
    USE SIGNAL ;
    PORT
      LAYER M5 ;
        RECT  41.52 189.996 41.544 190.08 ;
    END
  END f_d[98]
  PIN f_d[99]
    DIRECTION INPUT ;
    USE SIGNAL ;
    PORT
      LAYER M5 ;
        RECT  41.808 189.996 41.832 190.08 ;
    END
  END f_d[99]
  PIN f_d[9]
    DIRECTION INPUT ;
    USE SIGNAL ;
    PORT
      LAYER M5 ;
        RECT  16.416 189.996 16.44 190.08 ;
    END
  END f_d[9]
  PIN f_t[0]
    DIRECTION INPUT ;
    USE SIGNAL ;
    PORT
      LAYER M5 ;
        RECT  5.424 189.996 5.448 190.08 ;
    END
  END f_t[0]
  PIN f_t[1]
    DIRECTION INPUT ;
    USE SIGNAL ;
    PORT
      LAYER M5 ;
        RECT  5.712 189.996 5.736 190.08 ;
    END
  END f_t[1]
  PIN f_t[2]
    DIRECTION INPUT ;
    USE SIGNAL ;
    PORT
      LAYER M5 ;
        RECT  6 189.996 6.024 190.08 ;
    END
  END f_t[2]
  PIN f_t[3]
    DIRECTION INPUT ;
    USE SIGNAL ;
    PORT
      LAYER M5 ;
        RECT  6.288 189.996 6.312 190.08 ;
    END
  END f_t[3]
  PIN f_t[4]
    DIRECTION INPUT ;
    USE SIGNAL ;
    PORT
      LAYER M5 ;
        RECT  6.576 189.996 6.6 190.08 ;
    END
  END f_t[4]
  PIN f_t[5]
    DIRECTION INPUT ;
    USE SIGNAL ;
    PORT
      LAYER M5 ;
        RECT  6.864 189.996 6.888 190.08 ;
    END
  END f_t[5]
  PIN f_v[0]
    DIRECTION INPUT ;
    USE SIGNAL ;
    PORT
      LAYER M5 ;
        RECT  4.608 189.996 4.632 190.08 ;
    END
  END f_v[0]
  PIN f_v[1]
    DIRECTION INPUT ;
    USE SIGNAL ;
    PORT
      LAYER M5 ;
        RECT  4.896 189.996 4.92 190.08 ;
    END
  END f_v[1]
  PIN f_v[2]
    DIRECTION INPUT ;
    USE SIGNAL ;
    PORT
      LAYER M5 ;
        RECT  5.184 189.996 5.208 190.08 ;
    END
  END f_v[2]
  PIN fault
    DIRECTION OUTPUT ;
    USE SIGNAL ;
    PORT
      LAYER M5 ;
        RECT  177.072 189.996 177.096 190.08 ;
    END
  END fault
  PIN go
    DIRECTION INPUT ;
    USE SIGNAL ;
    PORT
      LAYER M5 ;
        RECT  4.32 189.996 4.344 190.08 ;
    END
  END go
  PIN r_dd[0]
    DIRECTION OUTPUT ;
    USE SIGNAL ;
    PORT
      LAYER M5 ;
        RECT  168.048 189.996 168.072 190.08 ;
    END
  END r_dd[0]
  PIN r_dd[10]
    DIRECTION OUTPUT ;
    USE SIGNAL ;
    PORT
      LAYER M5 ;
        RECT  170.88 189.996 170.904 190.08 ;
    END
  END r_dd[10]
  PIN r_dd[11]
    DIRECTION OUTPUT ;
    USE SIGNAL ;
    PORT
      LAYER M5 ;
        RECT  171.168 189.996 171.192 190.08 ;
    END
  END r_dd[11]
  PIN r_dd[12]
    DIRECTION OUTPUT ;
    USE SIGNAL ;
    PORT
      LAYER M5 ;
        RECT  171.456 189.996 171.48 190.08 ;
    END
  END r_dd[12]
  PIN r_dd[13]
    DIRECTION OUTPUT ;
    USE SIGNAL ;
    PORT
      LAYER M5 ;
        RECT  171.696 189.996 171.72 190.08 ;
    END
  END r_dd[13]
  PIN r_dd[14]
    DIRECTION OUTPUT ;
    USE SIGNAL ;
    PORT
      LAYER M5 ;
        RECT  171.984 189.996 172.008 190.08 ;
    END
  END r_dd[14]
  PIN r_dd[15]
    DIRECTION OUTPUT ;
    USE SIGNAL ;
    PORT
      LAYER M5 ;
        RECT  172.272 189.996 172.296 190.08 ;
    END
  END r_dd[15]
  PIN r_dd[16]
    DIRECTION OUTPUT ;
    USE SIGNAL ;
    PORT
      LAYER M5 ;
        RECT  172.56 189.996 172.584 190.08 ;
    END
  END r_dd[16]
  PIN r_dd[17]
    DIRECTION OUTPUT ;
    USE SIGNAL ;
    PORT
      LAYER M5 ;
        RECT  172.848 189.996 172.872 190.08 ;
    END
  END r_dd[17]
  PIN r_dd[18]
    DIRECTION OUTPUT ;
    USE SIGNAL ;
    PORT
      LAYER M5 ;
        RECT  173.136 189.996 173.16 190.08 ;
    END
  END r_dd[18]
  PIN r_dd[19]
    DIRECTION OUTPUT ;
    USE SIGNAL ;
    PORT
      LAYER M5 ;
        RECT  173.424 189.996 173.448 190.08 ;
    END
  END r_dd[19]
  PIN r_dd[1]
    DIRECTION OUTPUT ;
    USE SIGNAL ;
    PORT
      LAYER M5 ;
        RECT  168.336 189.996 168.36 190.08 ;
    END
  END r_dd[1]
  PIN r_dd[20]
    DIRECTION OUTPUT ;
    USE SIGNAL ;
    PORT
      LAYER M5 ;
        RECT  173.712 189.996 173.736 190.08 ;
    END
  END r_dd[20]
  PIN r_dd[21]
    DIRECTION OUTPUT ;
    USE SIGNAL ;
    PORT
      LAYER M5 ;
        RECT  173.952 189.996 173.976 190.08 ;
    END
  END r_dd[21]
  PIN r_dd[22]
    DIRECTION OUTPUT ;
    USE SIGNAL ;
    PORT
      LAYER M5 ;
        RECT  174.24 189.996 174.264 190.08 ;
    END
  END r_dd[22]
  PIN r_dd[23]
    DIRECTION OUTPUT ;
    USE SIGNAL ;
    PORT
      LAYER M5 ;
        RECT  174.528 189.996 174.552 190.08 ;
    END
  END r_dd[23]
  PIN r_dd[24]
    DIRECTION OUTPUT ;
    USE SIGNAL ;
    PORT
      LAYER M5 ;
        RECT  174.816 189.996 174.84 190.08 ;
    END
  END r_dd[24]
  PIN r_dd[25]
    DIRECTION OUTPUT ;
    USE SIGNAL ;
    PORT
      LAYER M5 ;
        RECT  175.104 189.996 175.128 190.08 ;
    END
  END r_dd[25]
  PIN r_dd[26]
    DIRECTION OUTPUT ;
    USE SIGNAL ;
    PORT
      LAYER M5 ;
        RECT  175.392 189.996 175.416 190.08 ;
    END
  END r_dd[26]
  PIN r_dd[27]
    DIRECTION OUTPUT ;
    USE SIGNAL ;
    PORT
      LAYER M5 ;
        RECT  175.68 189.996 175.704 190.08 ;
    END
  END r_dd[27]
  PIN r_dd[28]
    DIRECTION OUTPUT ;
    USE SIGNAL ;
    PORT
      LAYER M5 ;
        RECT  175.968 189.996 175.992 190.08 ;
    END
  END r_dd[28]
  PIN r_dd[29]
    DIRECTION OUTPUT ;
    USE SIGNAL ;
    PORT
      LAYER M5 ;
        RECT  176.208 189.996 176.232 190.08 ;
    END
  END r_dd[29]
  PIN r_dd[2]
    DIRECTION OUTPUT ;
    USE SIGNAL ;
    PORT
      LAYER M5 ;
        RECT  168.624 189.996 168.648 190.08 ;
    END
  END r_dd[2]
  PIN r_dd[30]
    DIRECTION OUTPUT ;
    USE SIGNAL ;
    PORT
      LAYER M5 ;
        RECT  176.496 189.996 176.52 190.08 ;
    END
  END r_dd[30]
  PIN r_dd[31]
    DIRECTION OUTPUT ;
    USE SIGNAL ;
    PORT
      LAYER M5 ;
        RECT  176.784 189.996 176.808 190.08 ;
    END
  END r_dd[31]
  PIN r_dd[3]
    DIRECTION OUTPUT ;
    USE SIGNAL ;
    PORT
      LAYER M5 ;
        RECT  168.912 189.996 168.936 190.08 ;
    END
  END r_dd[3]
  PIN r_dd[4]
    DIRECTION OUTPUT ;
    USE SIGNAL ;
    PORT
      LAYER M5 ;
        RECT  169.2 189.996 169.224 190.08 ;
    END
  END r_dd[4]
  PIN r_dd[5]
    DIRECTION OUTPUT ;
    USE SIGNAL ;
    PORT
      LAYER M5 ;
        RECT  169.44 189.996 169.464 190.08 ;
    END
  END r_dd[5]
  PIN r_dd[6]
    DIRECTION OUTPUT ;
    USE SIGNAL ;
    PORT
      LAYER M5 ;
        RECT  169.728 189.996 169.752 190.08 ;
    END
  END r_dd[6]
  PIN r_dd[7]
    DIRECTION OUTPUT ;
    USE SIGNAL ;
    PORT
      LAYER M5 ;
        RECT  170.016 189.996 170.04 190.08 ;
    END
  END r_dd[7]
  PIN r_dd[8]
    DIRECTION OUTPUT ;
    USE SIGNAL ;
    PORT
      LAYER M5 ;
        RECT  170.304 189.996 170.328 190.08 ;
    END
  END r_dd[8]
  PIN r_dd[9]
    DIRECTION OUTPUT ;
    USE SIGNAL ;
    PORT
      LAYER M5 ;
        RECT  170.592 189.996 170.616 190.08 ;
    END
  END r_dd[9]
  PIN r_hh[0]
    DIRECTION OUTPUT ;
    USE SIGNAL ;
    PORT
      LAYER M5 ;
        RECT  150 189.996 150.024 190.08 ;
    END
  END r_hh[0]
  PIN r_hh[10]
    DIRECTION OUTPUT ;
    USE SIGNAL ;
    PORT
      LAYER M5 ;
        RECT  152.832 189.996 152.856 190.08 ;
    END
  END r_hh[10]
  PIN r_hh[11]
    DIRECTION OUTPUT ;
    USE SIGNAL ;
    PORT
      LAYER M5 ;
        RECT  153.12 189.996 153.144 190.08 ;
    END
  END r_hh[11]
  PIN r_hh[12]
    DIRECTION OUTPUT ;
    USE SIGNAL ;
    PORT
      LAYER M5 ;
        RECT  153.408 189.996 153.432 190.08 ;
    END
  END r_hh[12]
  PIN r_hh[13]
    DIRECTION OUTPUT ;
    USE SIGNAL ;
    PORT
      LAYER M5 ;
        RECT  153.696 189.996 153.72 190.08 ;
    END
  END r_hh[13]
  PIN r_hh[14]
    DIRECTION OUTPUT ;
    USE SIGNAL ;
    PORT
      LAYER M5 ;
        RECT  153.984 189.996 154.008 190.08 ;
    END
  END r_hh[14]
  PIN r_hh[15]
    DIRECTION OUTPUT ;
    USE SIGNAL ;
    PORT
      LAYER M5 ;
        RECT  154.224 189.996 154.248 190.08 ;
    END
  END r_hh[15]
  PIN r_hh[16]
    DIRECTION OUTPUT ;
    USE SIGNAL ;
    PORT
      LAYER M5 ;
        RECT  154.512 189.996 154.536 190.08 ;
    END
  END r_hh[16]
  PIN r_hh[17]
    DIRECTION OUTPUT ;
    USE SIGNAL ;
    PORT
      LAYER M5 ;
        RECT  154.8 189.996 154.824 190.08 ;
    END
  END r_hh[17]
  PIN r_hh[18]
    DIRECTION OUTPUT ;
    USE SIGNAL ;
    PORT
      LAYER M5 ;
        RECT  155.088 189.996 155.112 190.08 ;
    END
  END r_hh[18]
  PIN r_hh[19]
    DIRECTION OUTPUT ;
    USE SIGNAL ;
    PORT
      LAYER M5 ;
        RECT  155.376 189.996 155.4 190.08 ;
    END
  END r_hh[19]
  PIN r_hh[1]
    DIRECTION OUTPUT ;
    USE SIGNAL ;
    PORT
      LAYER M5 ;
        RECT  150.288 189.996 150.312 190.08 ;
    END
  END r_hh[1]
  PIN r_hh[20]
    DIRECTION OUTPUT ;
    USE SIGNAL ;
    PORT
      LAYER M5 ;
        RECT  155.664 189.996 155.688 190.08 ;
    END
  END r_hh[20]
  PIN r_hh[21]
    DIRECTION OUTPUT ;
    USE SIGNAL ;
    PORT
      LAYER M5 ;
        RECT  155.952 189.996 155.976 190.08 ;
    END
  END r_hh[21]
  PIN r_hh[22]
    DIRECTION OUTPUT ;
    USE SIGNAL ;
    PORT
      LAYER M5 ;
        RECT  156.24 189.996 156.264 190.08 ;
    END
  END r_hh[22]
  PIN r_hh[23]
    DIRECTION OUTPUT ;
    USE SIGNAL ;
    PORT
      LAYER M5 ;
        RECT  156.48 189.996 156.504 190.08 ;
    END
  END r_hh[23]
  PIN r_hh[24]
    DIRECTION OUTPUT ;
    USE SIGNAL ;
    PORT
      LAYER M5 ;
        RECT  156.768 189.996 156.792 190.08 ;
    END
  END r_hh[24]
  PIN r_hh[25]
    DIRECTION OUTPUT ;
    USE SIGNAL ;
    PORT
      LAYER M5 ;
        RECT  157.056 189.996 157.08 190.08 ;
    END
  END r_hh[25]
  PIN r_hh[26]
    DIRECTION OUTPUT ;
    USE SIGNAL ;
    PORT
      LAYER M5 ;
        RECT  157.344 189.996 157.368 190.08 ;
    END
  END r_hh[26]
  PIN r_hh[27]
    DIRECTION OUTPUT ;
    USE SIGNAL ;
    PORT
      LAYER M5 ;
        RECT  157.632 189.996 157.656 190.08 ;
    END
  END r_hh[27]
  PIN r_hh[28]
    DIRECTION OUTPUT ;
    USE SIGNAL ;
    PORT
      LAYER M5 ;
        RECT  157.92 189.996 157.944 190.08 ;
    END
  END r_hh[28]
  PIN r_hh[29]
    DIRECTION OUTPUT ;
    USE SIGNAL ;
    PORT
      LAYER M5 ;
        RECT  158.208 189.996 158.232 190.08 ;
    END
  END r_hh[29]
  PIN r_hh[2]
    DIRECTION OUTPUT ;
    USE SIGNAL ;
    PORT
      LAYER M5 ;
        RECT  150.576 189.996 150.6 190.08 ;
    END
  END r_hh[2]
  PIN r_hh[30]
    DIRECTION OUTPUT ;
    USE SIGNAL ;
    PORT
      LAYER M5 ;
        RECT  158.496 189.996 158.52 190.08 ;
    END
  END r_hh[30]
  PIN r_hh[31]
    DIRECTION OUTPUT ;
    USE SIGNAL ;
    PORT
      LAYER M5 ;
        RECT  158.736 189.996 158.76 190.08 ;
    END
  END r_hh[31]
  PIN r_hh[3]
    DIRECTION OUTPUT ;
    USE SIGNAL ;
    PORT
      LAYER M5 ;
        RECT  150.864 189.996 150.888 190.08 ;
    END
  END r_hh[3]
  PIN r_hh[4]
    DIRECTION OUTPUT ;
    USE SIGNAL ;
    PORT
      LAYER M5 ;
        RECT  151.152 189.996 151.176 190.08 ;
    END
  END r_hh[4]
  PIN r_hh[5]
    DIRECTION OUTPUT ;
    USE SIGNAL ;
    PORT
      LAYER M5 ;
        RECT  151.44 189.996 151.464 190.08 ;
    END
  END r_hh[5]
  PIN r_hh[6]
    DIRECTION OUTPUT ;
    USE SIGNAL ;
    PORT
      LAYER M5 ;
        RECT  151.728 189.996 151.752 190.08 ;
    END
  END r_hh[6]
  PIN r_hh[7]
    DIRECTION OUTPUT ;
    USE SIGNAL ;
    PORT
      LAYER M5 ;
        RECT  151.968 189.996 151.992 190.08 ;
    END
  END r_hh[7]
  PIN r_hh[8]
    DIRECTION OUTPUT ;
    USE SIGNAL ;
    PORT
      LAYER M5 ;
        RECT  152.256 189.996 152.28 190.08 ;
    END
  END r_hh[8]
  PIN r_hh[9]
    DIRECTION OUTPUT ;
    USE SIGNAL ;
    PORT
      LAYER M5 ;
        RECT  152.544 189.996 152.568 190.08 ;
    END
  END r_hh[9]
  PIN r_kk[0]
    DIRECTION OUTPUT ;
    USE SIGNAL ;
    PORT
      LAYER M5 ;
        RECT  159.024 189.996 159.048 190.08 ;
    END
  END r_kk[0]
  PIN r_kk[10]
    DIRECTION OUTPUT ;
    USE SIGNAL ;
    PORT
      LAYER M5 ;
        RECT  161.856 189.996 161.88 190.08 ;
    END
  END r_kk[10]
  PIN r_kk[11]
    DIRECTION OUTPUT ;
    USE SIGNAL ;
    PORT
      LAYER M5 ;
        RECT  162.144 189.996 162.168 190.08 ;
    END
  END r_kk[11]
  PIN r_kk[12]
    DIRECTION OUTPUT ;
    USE SIGNAL ;
    PORT
      LAYER M5 ;
        RECT  162.432 189.996 162.456 190.08 ;
    END
  END r_kk[12]
  PIN r_kk[13]
    DIRECTION OUTPUT ;
    USE SIGNAL ;
    PORT
      LAYER M5 ;
        RECT  162.72 189.996 162.744 190.08 ;
    END
  END r_kk[13]
  PIN r_kk[14]
    DIRECTION OUTPUT ;
    USE SIGNAL ;
    PORT
      LAYER M5 ;
        RECT  162.96 189.996 162.984 190.08 ;
    END
  END r_kk[14]
  PIN r_kk[15]
    DIRECTION OUTPUT ;
    USE SIGNAL ;
    PORT
      LAYER M5 ;
        RECT  163.248 189.996 163.272 190.08 ;
    END
  END r_kk[15]
  PIN r_kk[16]
    DIRECTION OUTPUT ;
    USE SIGNAL ;
    PORT
      LAYER M5 ;
        RECT  163.536 189.996 163.56 190.08 ;
    END
  END r_kk[16]
  PIN r_kk[17]
    DIRECTION OUTPUT ;
    USE SIGNAL ;
    PORT
      LAYER M5 ;
        RECT  163.824 189.996 163.848 190.08 ;
    END
  END r_kk[17]
  PIN r_kk[18]
    DIRECTION OUTPUT ;
    USE SIGNAL ;
    PORT
      LAYER M5 ;
        RECT  164.112 189.996 164.136 190.08 ;
    END
  END r_kk[18]
  PIN r_kk[19]
    DIRECTION OUTPUT ;
    USE SIGNAL ;
    PORT
      LAYER M5 ;
        RECT  164.4 189.996 164.424 190.08 ;
    END
  END r_kk[19]
  PIN r_kk[1]
    DIRECTION OUTPUT ;
    USE SIGNAL ;
    PORT
      LAYER M5 ;
        RECT  159.312 189.996 159.336 190.08 ;
    END
  END r_kk[1]
  PIN r_kk[20]
    DIRECTION OUTPUT ;
    USE SIGNAL ;
    PORT
      LAYER M5 ;
        RECT  164.688 189.996 164.712 190.08 ;
    END
  END r_kk[20]
  PIN r_kk[21]
    DIRECTION OUTPUT ;
    USE SIGNAL ;
    PORT
      LAYER M5 ;
        RECT  164.976 189.996 165 190.08 ;
    END
  END r_kk[21]
  PIN r_kk[22]
    DIRECTION OUTPUT ;
    USE SIGNAL ;
    PORT
      LAYER M5 ;
        RECT  165.216 189.996 165.24 190.08 ;
    END
  END r_kk[22]
  PIN r_kk[23]
    DIRECTION OUTPUT ;
    USE SIGNAL ;
    PORT
      LAYER M5 ;
        RECT  165.504 189.996 165.528 190.08 ;
    END
  END r_kk[23]
  PIN r_kk[24]
    DIRECTION OUTPUT ;
    USE SIGNAL ;
    PORT
      LAYER M5 ;
        RECT  165.792 189.996 165.816 190.08 ;
    END
  END r_kk[24]
  PIN r_kk[25]
    DIRECTION OUTPUT ;
    USE SIGNAL ;
    PORT
      LAYER M5 ;
        RECT  166.08 189.996 166.104 190.08 ;
    END
  END r_kk[25]
  PIN r_kk[26]
    DIRECTION OUTPUT ;
    USE SIGNAL ;
    PORT
      LAYER M5 ;
        RECT  166.368 189.996 166.392 190.08 ;
    END
  END r_kk[26]
  PIN r_kk[27]
    DIRECTION OUTPUT ;
    USE SIGNAL ;
    PORT
      LAYER M5 ;
        RECT  166.656 189.996 166.68 190.08 ;
    END
  END r_kk[27]
  PIN r_kk[28]
    DIRECTION OUTPUT ;
    USE SIGNAL ;
    PORT
      LAYER M5 ;
        RECT  166.944 189.996 166.968 190.08 ;
    END
  END r_kk[28]
  PIN r_kk[29]
    DIRECTION OUTPUT ;
    USE SIGNAL ;
    PORT
      LAYER M5 ;
        RECT  167.232 189.996 167.256 190.08 ;
    END
  END r_kk[29]
  PIN r_kk[2]
    DIRECTION OUTPUT ;
    USE SIGNAL ;
    PORT
      LAYER M5 ;
        RECT  159.6 189.996 159.624 190.08 ;
    END
  END r_kk[2]
  PIN r_kk[30]
    DIRECTION OUTPUT ;
    USE SIGNAL ;
    PORT
      LAYER M5 ;
        RECT  167.472 189.996 167.496 190.08 ;
    END
  END r_kk[30]
  PIN r_kk[31]
    DIRECTION OUTPUT ;
    USE SIGNAL ;
    PORT
      LAYER M5 ;
        RECT  167.76 189.996 167.784 190.08 ;
    END
  END r_kk[31]
  PIN r_kk[3]
    DIRECTION OUTPUT ;
    USE SIGNAL ;
    PORT
      LAYER M5 ;
        RECT  159.888 189.996 159.912 190.08 ;
    END
  END r_kk[3]
  PIN r_kk[4]
    DIRECTION OUTPUT ;
    USE SIGNAL ;
    PORT
      LAYER M5 ;
        RECT  160.176 189.996 160.2 190.08 ;
    END
  END r_kk[4]
  PIN r_kk[5]
    DIRECTION OUTPUT ;
    USE SIGNAL ;
    PORT
      LAYER M5 ;
        RECT  160.464 189.996 160.488 190.08 ;
    END
  END r_kk[5]
  PIN r_kk[6]
    DIRECTION OUTPUT ;
    USE SIGNAL ;
    PORT
      LAYER M5 ;
        RECT  160.704 189.996 160.728 190.08 ;
    END
  END r_kk[6]
  PIN r_kk[7]
    DIRECTION OUTPUT ;
    USE SIGNAL ;
    PORT
      LAYER M5 ;
        RECT  160.992 189.996 161.016 190.08 ;
    END
  END r_kk[7]
  PIN r_kk[8]
    DIRECTION OUTPUT ;
    USE SIGNAL ;
    PORT
      LAYER M5 ;
        RECT  161.28 189.996 161.304 190.08 ;
    END
  END r_kk[8]
  PIN r_kk[9]
    DIRECTION OUTPUT ;
    USE SIGNAL ;
    PORT
      LAYER M5 ;
        RECT  161.568 189.996 161.592 190.08 ;
    END
  END r_kk[9]
  PIN r_v
    DIRECTION OUTPUT ;
    USE SIGNAL ;
    PORT
      LAYER M5 ;
        RECT  149.76 189.996 149.784 190.08 ;
    END
  END r_v
  PIN rst_n
    DIRECTION INPUT ;
    USE SIGNAL ;
    PORT
      LAYER M5 ;
        RECT  81.84 189.996 81.864 190.08 ;
    END
  END rst_n
  PIN VDD
    DIRECTION INOUT ;
    USE POWER ;
    PORT
      LAYER M5 ;
        RECT  174.996 4.311 175.116 185.769 ;
        RECT  170.676 4.311 170.796 185.769 ;
        RECT  166.356 4.311 166.476 185.769 ;
        RECT  162.036 4.311 162.156 185.769 ;
        RECT  157.716 4.311 157.836 185.769 ;
        RECT  153.396 4.311 153.516 185.769 ;
        RECT  149.076 4.311 149.196 185.769 ;
        RECT  144.756 4.311 144.876 185.769 ;
        RECT  140.436 4.311 140.556 185.769 ;
        RECT  136.116 4.311 136.236 185.769 ;
        RECT  131.796 4.311 131.916 185.769 ;
        RECT  127.476 4.311 127.596 185.769 ;
        RECT  123.156 4.311 123.276 185.769 ;
        RECT  118.836 4.311 118.956 185.769 ;
        RECT  114.516 4.311 114.636 185.769 ;
        RECT  110.196 4.311 110.316 185.769 ;
        RECT  105.876 4.311 105.996 185.769 ;
        RECT  101.556 4.311 101.676 185.769 ;
        RECT  97.236 4.311 97.356 185.769 ;
        RECT  92.916 4.311 93.036 185.769 ;
        RECT  88.596 4.311 88.716 185.769 ;
        RECT  84.276 4.311 84.396 185.769 ;
        RECT  79.956 4.311 80.076 185.769 ;
        RECT  75.636 4.311 75.756 185.769 ;
        RECT  71.316 4.311 71.436 185.769 ;
        RECT  66.996 4.311 67.116 185.769 ;
        RECT  62.676 4.311 62.796 185.769 ;
        RECT  58.356 4.311 58.476 185.769 ;
        RECT  54.036 4.311 54.156 185.769 ;
        RECT  49.716 4.311 49.836 185.769 ;
        RECT  45.396 4.311 45.516 185.769 ;
        RECT  41.076 4.311 41.196 185.769 ;
        RECT  36.756 4.311 36.876 185.769 ;
        RECT  32.436 4.311 32.556 185.769 ;
        RECT  28.116 4.311 28.236 185.769 ;
        RECT  23.796 4.311 23.916 185.769 ;
        RECT  19.476 4.311 19.596 185.769 ;
        RECT  15.156 4.311 15.276 185.769 ;
        RECT  10.836 4.311 10.956 185.769 ;
        RECT  6.516 4.311 6.636 185.769 ;
    END
  END VDD
  PIN VSS
    DIRECTION INOUT ;
    USE GROUND ;
    PORT
      LAYER M5 ;
        RECT  174.804 4.297 174.924 185.783 ;
        RECT  170.484 4.297 170.604 185.783 ;
        RECT  166.164 4.297 166.284 185.783 ;
        RECT  161.844 4.297 161.964 185.783 ;
        RECT  157.524 4.297 157.644 185.783 ;
        RECT  153.204 4.297 153.324 185.783 ;
        RECT  148.884 4.297 149.004 185.783 ;
        RECT  144.564 4.297 144.684 185.783 ;
        RECT  140.244 4.297 140.364 185.783 ;
        RECT  135.924 4.297 136.044 185.783 ;
        RECT  131.604 4.297 131.724 185.783 ;
        RECT  127.284 4.297 127.404 185.783 ;
        RECT  122.964 4.297 123.084 185.783 ;
        RECT  118.644 4.297 118.764 185.783 ;
        RECT  114.324 4.297 114.444 185.783 ;
        RECT  110.004 4.297 110.124 185.783 ;
        RECT  105.684 4.297 105.804 185.783 ;
        RECT  101.364 4.297 101.484 185.783 ;
        RECT  97.044 4.297 97.164 185.783 ;
        RECT  92.724 4.297 92.844 185.783 ;
        RECT  88.404 4.297 88.524 185.783 ;
        RECT  84.084 4.297 84.204 185.783 ;
        RECT  79.764 4.297 79.884 185.783 ;
        RECT  75.444 4.297 75.564 185.783 ;
        RECT  71.124 4.297 71.244 185.783 ;
        RECT  66.804 4.297 66.924 185.783 ;
        RECT  62.484 4.297 62.604 185.783 ;
        RECT  58.164 4.297 58.284 185.783 ;
        RECT  53.844 4.297 53.964 185.783 ;
        RECT  49.524 4.297 49.644 185.783 ;
        RECT  45.204 4.297 45.324 185.783 ;
        RECT  40.884 4.297 41.004 185.783 ;
        RECT  36.564 4.297 36.684 185.783 ;
        RECT  32.244 4.297 32.364 185.783 ;
        RECT  27.924 4.297 28.044 185.783 ;
        RECT  23.604 4.297 23.724 185.783 ;
        RECT  19.284 4.297 19.404 185.783 ;
        RECT  14.964 4.297 15.084 185.783 ;
        RECT  10.644 4.297 10.764 185.783 ;
        RECT  6.324 4.297 6.444 185.783 ;
    END
  END VSS
  OBS
    LAYER RVTN ;
     RECT  4.309 4.297 177.12 190.08 ;
    LAYER RVTP ;
     RECT  4.309 4.297 177.12 190.08 ;
    LAYER M1 ;
     RECT  4.309 4.297 177.12 190.08 ;
    LAYER M2 ;
     RECT  4.309 4.297 177.12 190.08 ;
    LAYER M3 ;
     RECT  4.309 4.297 177.12 190.08 ;
    LAYER M4 ;
     RECT  4.309 4.297 177.12 190.08 ;
    LAYER M5 ;
     RECT  4.309 4.297 177.12 190.08 ;
  END
END ot_s81dv_eng_finish
END LIBRARY
